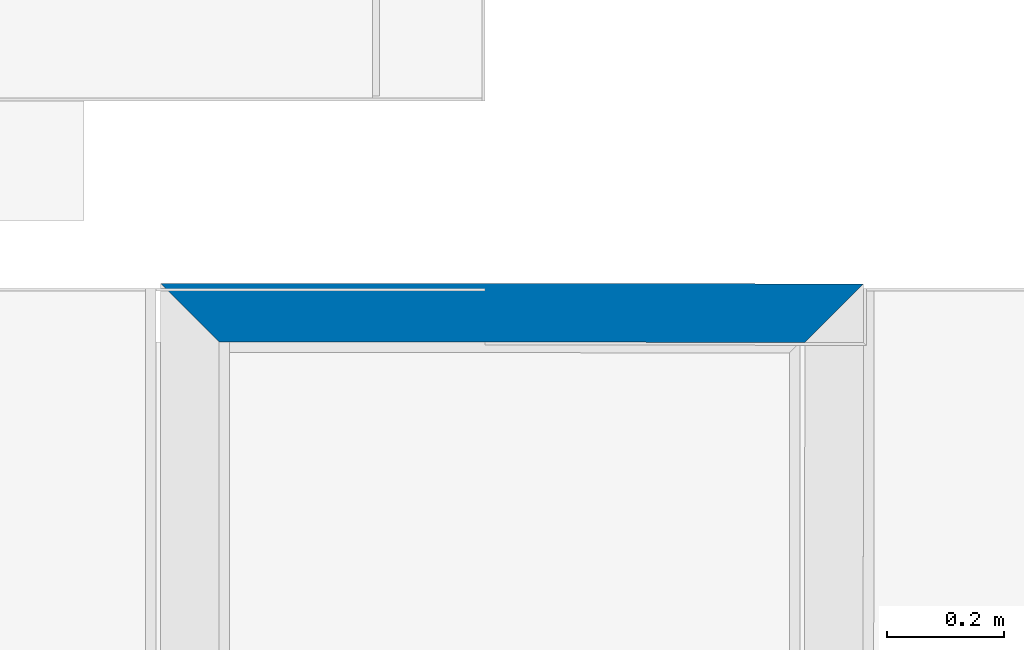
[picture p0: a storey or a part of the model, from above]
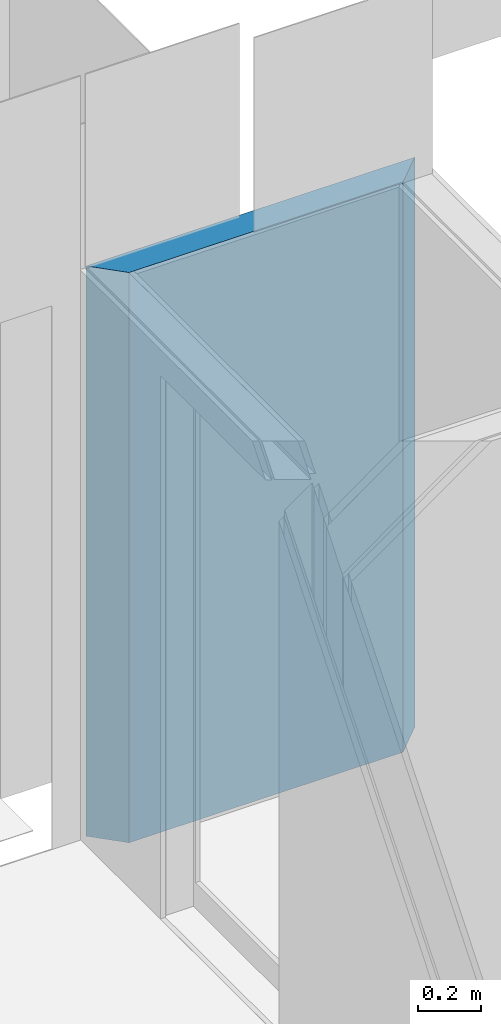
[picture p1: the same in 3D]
Properties of the parts of a building model (IFC2X3), part 1 of 2

# File
Description: ViewDefinition [CoordinationView_V2.0, SpaceBoundary2ndLevelAddOnView], Option [Elements to export: Filtered elements], Option [Partial Structure Display: Entire Model], Option [IFC Domain: All], Option [Structural Function: All Elements], Option [Convert Grid elements: On], Option [Convert IFC Annotations and Archicad 2D elements: Off], Option [Convert 2D symbols of Doors and Windows: Off], Option [Export geometries that Participates in Collision Detection only: Off], Option [Split complex elements: On], Option [IFC Domain For Space Containment: Custom], Option [Elements in Solid Element Operations: Extruded/revolved], Option [Elements with junctions: Extruded/revolved without junctions], Option [IFC Model position: Survey Point and Project Origin], Option [Curtain Wall export mode: Container Element], Option [Railing export mode: Container Element], Option [Stair export mode: Container Element], Option [Properties To Export: All properties], Option [Space containment: Off], Option [Geometry to type objects: Off], Option [Element Properties: Visible Only], Option [Building Material Properties: Off], Option [Element Parameters: Off], Option [Component Parameters: Off], Option [IFC Base Quantities: Off], Option [Door Window Parameters: On], Option [IFC Space boundaries: On], Option [Archicad Zone Categories as IFC Space classification data: Off], Option [Element Classifications: On]
File name: C:\Users\karle\Documents\KARLERK TARBE OÜ\Projektid\Ilmajaam\Ilmajaam TP\355_TP_SA_Paldiski-mnt-245-põrandad-seinad-20231201.ifc
Time: 2023-12-01T14:40:17
Author: Andres Rihe (allikirjastatud digitaalselt)
Organization: Building Designer Office
Written by: DDS_IFC v3.0
Made in: IFC file generated by Graphisoft Archicad 26.0.0 INT FULL Windows version (IFC add-on version: 4019 INT FULL).
Authorization: Andres Rihe (allikirjastatud digitaalselt)

# IfcProject, Ilmavaatlusjaama peahoone rekonstrueerimine
Description: Arhitektuur; Phase: Eelprojekt

# IfcSite, Paldiski mnt 245/1, Tallinn, Harjumaa
Description: Ühiskondlike ehitiste maa 100%; RefLatitude: 59, 26, 0, 0; RefLongitude: 24, 45, 0, 0; RefElevation: 0 mm; Classification: C Existing site/buildings/services (CAWS); 1.0.1 IfcSite (kinnistu) (RKAS BIM + ARCHICAD Classification 25 + v 2.0)
AR_Kinnistu - 010_Katastritunnus: 78406:605:0160; 020_Pindala: 24079 m2; 025_Max_kõrgus: 8600 mm; 015_Ehitatav_pindala: 1045.7 m2

# IfcBuilding, RKAS Hoone üldnimetus (kasutust iseloomustav) -> IFC Project Manager -> SOLIBRI
Classification: 1.0.2 IfcBuilding (hoone) (RKAS BIM + ARCHICAD Classification 25 + v 2.0)
AR_Hoone - 035_Sprinkler: no; 001_Nimetus: 12201 Büroohoone; 030_Hoone_aadress: Paldiski mnt 245/1 (katastriüksuse tunnus 78406:605:0160 ), Haabersti linnaosa, Tallinn, Eesti Vabariik; 040_Kõrgus: 8600 mm; ?: 1004.1 m2; 050_Neto_pindala: 1090.4 m2; 055_Neto_ruumala: 5563.9 m3

# IfcBuildingStorey (4)
In: RKAS Hoone üldnimetus (kasutust iseloomustav) -> IFC Project Manager -> SOLIBRI
Name | Elevation (mm) | Classification
Katusekorrus | 6240
Esimene korrus | 0 | 1.0.3 IfcBuildingStorey (korrus) (RKAS BIM + ARCHICAD Classification 25 + v 2.0)
Vundament | -1200 | 1.0.3 IfcBuildingStorey (korrus) (RKAS BIM + ARCHICAD Classification 25 + v 2.0)
Teine korrus | 3300 | 1.0.3 IfcBuildingStorey (korrus) (RKAS BIM + ARCHICAD Classification 25 + v 2.0)

# IfcBuildingElementProxy: Cube 26, REEPER
In: Esimene korrus
Classification: 1.02.1 IfcBuildingElementProxyType (reeper) (RKAS BIM + ARCHICAD Classification)
AR - 001_Nimetus: REEPER
Pset_BuildingElementProxyCommon - Reference: Cube 26
AR_Reeper - 01_X-(L-EST): 3000; 02_Y-(L-EST): 1000; 03_Z-(EH2000): 7000; 04_Nurk(◦): 0
AC_Pset_RenovationAndPhasing - Renovation Status: New

# IfcBuildingElementProxy: SA- PM-4 porivaip 20, PM-4
In: Teine korrus
Classification: 1.14 IfcOpeningElement (avaelement) (RKAS BIM + ARCHICAD Classification); Material: SA- PM-4 porivaip
Pset_BuildingElementProxyCommon - Reference: SA- PM-4 porivaip
AR - 001_Nimetus: PM-4
AC_Pset_RenovationAndPhasing - Renovation Status: New

# IfcBuildingElementProxy: SA- PM-7 plaat 15x15 8, PM-7
In: Teine korrus
Classification: 1.14 IfcOpeningElement (avaelement) (RKAS BIM + ARCHICAD Classification); Material: SA- PM-7 plaat 15x15
Pset_BuildingElementProxyCommon - Reference: SA- PM-7 plaat 15x15
AR - 001_Nimetus: Põrandakatte materjal
AC_Pset_RenovationAndPhasing - Renovation Status: New

# IfcCovering: GENERIC - PREFABRICATED (106)
Type - PredefinedType: CLADDING
Classification: 1.05 IfcCoveringType.CLADDING (seina viimistlus) (RKAS BIM + ARCHICAD Classification); Material: GENERIC - PREFABRICATED
AR_Viimistlus - 215_Tulekindlusklass: B-s1,d0; 230_Niiskuskindel: no; 200_Materjal (MUDELIS): GENERIC - PREFABRICATED
AC_Pset_RenovationAndPhasing - Renovation Status: New
Name | In | Reference | AR_Viimistlus, 001_Nimetus = AR, 001_Nimetus | 200_Materjal | 205_Tähis | 220_Viimistlus | 900_Tootja | 905_Mudel | 910_Tooteinfo = 915_Kasutus-ja_hooldusjuhend | 240_Märghõõrdekindlus | 245_Aluspind | 210_Paksus (mm)
SM5 | Teine korrus | SM5 | Seinavärv | Veepõhine värv | SM5 | Poolmatt NCS S 1002-y20r (soe valge) | Tikkurila | Vivacolor interior | https://tikkurila.ee/ | 1.klass | Pahteldatud kipsplaat/sein | 1
105 x SM1 | Esimene korrus | GENERIC - PREFABRICATED | Seinapaneel | Akustiline vilt, spoon | SM1 | Tehase viimistlus | Vaga | Vesi | https://vaga-panel.ee/vaga-vesi/ | Undefined | Viimistletud sein | 23

# IfcCovering: KON-00_GENEERILINE - KONSTRUKTSIOON 100 (4)
In: Esimene korrus
Type - PredefinedType: CLADDING
Classification: 1.05 IfcCoveringType.CLADDING (seina viimistlus) (RKAS BIM + ARCHICAD Classification); Material: KON-00_GENEERILINE - KONSTRUKTSIOON
AC_Pset_RenovationAndPhasing - Renovation Status: Existing
Pset_CoveringCommon - Reference: KON-00; TotalThickness: 100 mm
AR_Viimistlus - 230_Niiskuskindel: no; 900_Tootja: Undefined; 905_Mudel: Undefined; 910_Tooteinfo: Undefined; 915_Kasutus-ja_hooldusjuhend: Undefined; 200_Materjal (MUDELIS): KON-00_GENEERILINE - KONSTRUKTSIOON
Name | AR_Viimistlus, 001_Nimetus = AR, 001_Nimetus | 225_Pindala (m2)
SM-3 | SM-3 | 4.35325
SM-3 | SM-3 | 2.45625
SS-59 | SS-59 | 4.35945
SS-63 | SS-63 | 2.18122

# IfcCovering: KON-00_GENEERILINE - KONSTRUKTSIOON 20, SM-1
In: Esimene korrus
Type - PredefinedType: CLADDING
Classification: 1.05 IfcCoveringType.CLADDING (seina viimistlus) (RKAS BIM + ARCHICAD Classification); Material: KON-00_GENEERILINE - KONSTRUKTSIOON
AR_Viimistlus - 230_Niiskuskindel: no; 001_Nimetus: SM-1; 900_Tootja: Undefined; 905_Mudel: Undefined; 910_Tooteinfo: Undefined; 915_Kasutus-ja_hooldusjuhend: Undefined; 200_Materjal (MUDELIS): KON-00_GENEERILINE - KONSTRUKTSIOON; 225_Pindala: 14.9372 m2
Pset_CoveringCommon - Reference: KON-00; TotalThickness: 20 mm
AR - 001_Nimetus: SM-1
AC_Pset_RenovationAndPhasing - Renovation Status: Existing

# IfcCovering: PL-2 10 x 60 (2)
In: Esimene korrus
Type - PredefinedType: CEILING
Classification: 1.04 IfcCoveringType.CEILING (ripplagi) (RKAS BIM + ARCHICAD Classification); Material: RAL 9007
Pset_CoveringCommon - Reference: RL-1; Material: Teras
AR_Viimistlus - 001_Nimetus: Ripplae liist; 235_Karkass: Undefined; 900_Tootja: Ecophon; 905_Mudel: T24, L24; 200_Materjal (MUDELIS): RAL 9007
AC_Pset_RenovationAndPhasing - Renovation Status: New
AR - 001_Nimetus: Ripplae liist

# IfcCovering: PL-5 4 x 70 (10)
In: Teine korrus
Type - PredefinedType: CEILING
Classification: 1.04 IfcCoveringType.CEILING (ripplagi) (RKAS BIM + ARCHICAD Classification); Material: SA- PM-2 vinüül hex
Pset_CoveringCommon - Reference: RL-1; Material: Teras
AR_Viimistlus - 001_Nimetus: Ripplae liist; 235_Karkass: Undefined; 900_Tootja: Ecophon; 905_Mudel: T24, L24; 200_Materjal (MUDELIS): SA- PM-2 vinüül hex
AR - 001_Nimetus: Ripplae liist
AC_Pset_RenovationAndPhasing - Renovation Status: New

# IfcCovering: SA- Laminaat SM13(beez laminaat) 12 (11)
In: Esimene korrus
Type - PredefinedType: CLADDING
Classification: 1.05 IfcCoveringType.CLADDING (seina viimistlus) (RKAS BIM + ARCHICAD Classification); Material: SA- Laminaat SM13(beez laminaat)
AR_Viimistlus - 230_Niiskuskindel: no; 001_Nimetus: Seinapaneel; 900_Tootja: abet laminati; 905_Mudel: abet laminati 478 grigio chiaro; fin sei.; 910_Tooteinfo: https://abetlaminati.com/; 915_Kasutus-ja_hooldusjuhend: https://abetlaminati.com/; 200_Materjal (MUDELIS): SA- Laminaat SM13(beez laminaat)
Pset_CoveringCommon - Reference: SA- Laminaat SM13(beez laminaat); TotalThickness: 12 mm
AR - 001_Nimetus: Seinapaneel
AC_Pset_RenovationAndPhasing - Renovation Status: New
Name | 225_Pindala (m2)
SM13 | 2.73049
SM13 | 2.07402
SM13 | 2.71213
SM13 | 2.35932
SM13 | 1.81026
SM13 | 0.977507
SM13 | 2.01618
SM13 | 2.77418
SM13 | 4.56394
SM13 | 3.01871
SM13 | 1.49167

# IfcCovering: SA- Laminaat SM2(kollane laminaat) 10 (2)
In: Esimene korrus
Type - PredefinedType: CLADDING
Classification: 1.05 IfcCoveringType.CLADDING (seina viimistlus) (RKAS BIM + ARCHICAD Classification); Material: SA- Laminaat SM2(kollane laminaat)
AR_Viimistlus - 230_Niiskuskindel: no; 001_Nimetus: Seinapaneel; 900_Tootja: Abet Laminati; 905_Mudel: 1801 giallo ocra; fin sei; 910_Tooteinfo: https://de.abetlaminati.com/decori/meg-colours-giallo-ocra-1801/; 915_Kasutus-ja_hooldusjuhend: https://de.abetlaminati.com/decori/meg-colours-giallo-ocra-1801/; 200_Materjal (MUDELIS): SA- Laminaat SM2(kollane laminaat)
AR - 001_Nimetus: Seinapaneel
AC_Pset_RenovationAndPhasing - Renovation Status: New
Pset_CoveringCommon - Reference: SA- Laminaat SM2(kollane laminaat); TotalThickness: 10 mm
Name | 225_Pindala (m2)
SM2 | 6.49925
SM2 | 2.78749

# IfcCovering: SA- Laminaat SM2(kollane laminaat) 12 (9)
Type - PredefinedType: CLADDING
Classification: 1.05 IfcCoveringType.CLADDING (seina viimistlus) (RKAS BIM + ARCHICAD Classification); Material: SA- Laminaat SM2(kollane laminaat)
AR_Viimistlus - 230_Niiskuskindel: no; 001_Nimetus: Seinapaneel; 900_Tootja: Abet Laminati; 905_Mudel: 1801 giallo ocra; fin sei; 910_Tooteinfo: https://de.abetlaminati.com/decori/meg-colours-giallo-ocra-1801/; 915_Kasutus-ja_hooldusjuhend: https://de.abetlaminati.com/decori/meg-colours-giallo-ocra-1801/; 200_Materjal (MUDELIS): SA- Laminaat SM2(kollane laminaat)
Pset_CoveringCommon - Reference: SA- Laminaat SM2(kollane laminaat); TotalThickness: 12 mm
AR - 001_Nimetus: Seinapaneel
AC_Pset_RenovationAndPhasing - Renovation Status: New
Name | In | 225_Pindala (m2)
SM2 | Teine korrus | 5.54141
SM2 | Teine korrus | 3.08782
SM2 | Teine korrus | 5.65656
SM2 | Teine korrus | 2.99939
SM2 | Esimene korrus | 2.3313
SM2 | Esimene korrus | 2.69522
SM2 | Esimene korrus | 3.71926
SM2 | Esimene korrus | 2.70783
SM2 | Esimene korrus | 1.31737

# IfcCovering: SA- Laminaat SM2(kollane laminaat) 12, SM2
In: Esimene korrus
Type - PredefinedType: FLOORING
Classification: 1.06 IfcCoveringType.FLOORING (põrandakatted) (RKAS BIM + ARCHICAD Classification); Material: SA- Laminaat SM2(kollane laminaat)
Pset_CoveringCommon - Reference: SA- Laminaat SM2(kollane laminaat); TotalThickness: 12 mm
AR_Viimistlus - 001_Nimetus: SM2; 200_Materjal: SA- Laminaat SM2(kollane laminaat); 205_Tähis: SA- Laminaat SM2(kollane laminaat); 215_Tulekindlusklass: Undefined; 220_Viimistlus: Undefined; 230_Niiskuskindel: no; 900_Tootja: Undefined; 905_Mudel: Undefined; 910_Tooteinfo: Undefined; 915_Kasutus-ja_hooldusjuhend: Undefined; 240_Märghõõrdekindlus: Undefined; 245_Aluspind: Undefined; 200_Materjal (MUDELIS): SA- Laminaat SM2(kollane laminaat); 225_Pindala: 0.213811 m2; 210_Paksus: 12 mm
AC_Pset_RenovationAndPhasing - Renovation Status: Existing
AR - 001_Nimetus: SM2

# IfcCovering: SA- Laminaat SM2(kollane laminaat) 20, SM2
In: Esimene korrus
Type - PredefinedType: FLOORING
Classification: 1.06 IfcCoveringType.FLOORING (põrandakatted) (RKAS BIM + ARCHICAD Classification); Material: SA- Laminaat SM2(kollane laminaat)
Pset_CoveringCommon - Reference: SA- Laminaat SM2(kollane laminaat); TotalThickness: 20 mm
AR_Viimistlus - 001_Nimetus: SM2; 200_Materjal: SA- Laminaat SM2(kollane laminaat); 205_Tähis: SA- Laminaat SM2(kollane laminaat); 215_Tulekindlusklass: Undefined; 220_Viimistlus: Undefined; 230_Niiskuskindel: no; 900_Tootja: Undefined; 905_Mudel: Undefined; 910_Tooteinfo: Undefined; 915_Kasutus-ja_hooldusjuhend: Undefined; 240_Märghõõrdekindlus: Undefined; 245_Aluspind: Undefined; 200_Materjal (MUDELIS): SA- Laminaat SM2(kollane laminaat); 225_Pindala: 0.435872 m2; 210_Paksus: 20 mm
AR - 001_Nimetus: SM2
AC_Pset_RenovationAndPhasing - Renovation Status: Existing

# IfcCovering: SA- Laminaat SM2(kollane laminaat) Polygonal, SM2
In: Teine korrus
Type - PredefinedType: CLADDING
Classification: 1.05 IfcCoveringType.CLADDING (seina viimistlus) (RKAS BIM + ARCHICAD Classification); Material: SA- Laminaat SM2(kollane laminaat)
Pset_CoveringCommon - Reference: SA- Laminaat SM2(kollane laminaat); TotalThickness: 12 mm
AR_Viimistlus - 001_Nimetus: Seinapaneel; 200_Materjal: 9mm mdf plaat kaetud kõrgsurve laminaadiga; 205_Tähis: SM2; 215_Tulekindlusklass: B-s1, d0; 220_Viimistlus: Puudub; 230_Niiskuskindel: yes; 900_Tootja: Abet Laminati; 905_Mudel: 1801 giallo ocra; fin sei; 910_Tooteinfo: https://de.abetlaminati.com/decori/meg-colours-giallo-ocra-1801/; 915_Kasutus-ja_hooldusjuhend: https://de.abetlaminati.com/decori/meg-colours-giallo-ocra-1801/; 240_Märghõõrdekindlus: 1.klass; 245_Aluspind: Kertopuu/teras karkass; 200_Materjal (MUDELIS): SA- Laminaat SM2(kollane laminaat); 225_Pindala: 3.47217 m2; 210_Paksus: 10 mm
AR - 001_Nimetus: Seinapaneel
AC_Pset_RenovationAndPhasing - Renovation Status: New

# IfcCovering: SA- Laudis SM3(vert. laudis) 18 (25)
In: Esimene korrus
Type - PredefinedType: CLADDING
Classification: 1.05 IfcCoveringType.CLADDING (seina viimistlus) (RKAS BIM + ARCHICAD Classification); Material: SA- Laudis SM3(vert. laudis)
Pset_CoveringCommon - TotalThickness: 18 mm
AR_Viimistlus - 230_Niiskuskindel: no; 900_Tootja: Puumarket; 200_Materjal (MUDELIS): SA- Laudis SM3(vert. laudis)
AC_Pset_RenovationAndPhasing - Renovation Status: New
Name | Reference | AR_Viimistlus, 001_Nimetus = AR, 001_Nimetus | 905_Mudel | 910_Tooteinfo = 915_Kasutus-ja_hooldusjuhend | 225_Pindala (m2)
SM14 | SA- Laudis SM3(vert. laudis) | Laudis | PTGV12x120, Tikkurila supi saunavaha (hall) ühe kihina | https://puumarket.ee/toode/sisevoodrilaud-kuusk-ptgv-12x120x3000mm/ | 1.56151
SM14 | SA- Laudis SM3(vert. laudis) | Laudis | PTGV12x120, Tikkurila supi saunavaha (hall) ühe kihina | https://puumarket.ee/toode/sisevoodrilaud-kuusk-ptgv-12x120x3000mm/ | 0.059546
SM14 | SA- Laudis SM3(vert. laudis) | Laudis | PTGV12x120, Tikkurila supi saunavaha (hall) ühe kihina | https://puumarket.ee/toode/sisevoodrilaud-kuusk-ptgv-12x120x3000mm/ | 0.0537709
SM14 | SA- Laudis SM3(vert. laudis) | Laudis | PTGV12x120, Tikkurila supi saunavaha (hall) ühe kihina | https://puumarket.ee/toode/sisevoodrilaud-kuusk-ptgv-12x120x3000mm/ | 0.347141
SM14 | SA- Laudis SM3(vert. laudis) | Laudis | PTGV12x120, Tikkurila supi saunavaha (hall) ühe kihina | https://puumarket.ee/toode/sisevoodrilaud-kuusk-ptgv-12x120x3000mm/ | 1.19245
2 x SM14 | SA- Laudis SM3(vert. laudis) | Laudis | PTGV12x120, Tikkurila supi saunavaha (hall) ühe kihina | https://puumarket.ee/toode/sisevoodrilaud-kuusk-ptgv-12x120x3000mm/ | 0
SM14 | SA- Laudis SM3(vert. laudis) | Laudis | PTGV12x120, Tikkurila supi saunavaha (hall) ühe kihina | https://puumarket.ee/toode/sisevoodrilaud-kuusk-ptgv-12x120x3000mm/ | 1.90986
SM14 | SA- Laudis SM3(vert. laudis) | Laudis | PTGV12x120, Tikkurila supi saunavaha (hall) ühe kihina | https://puumarket.ee/toode/sisevoodrilaud-kuusk-ptgv-12x120x3000mm/ | 2.18302
SM14 | SA- Laudis SM3(vert. laudis) | Laudis | PTGV12x120, Tikkurila supi saunavaha (hall) ühe kihina | https://puumarket.ee/toode/sisevoodrilaud-kuusk-ptgv-12x120x3000mm/ | 1.96838
SM14 | SA- Laudis SM3(vert. laudis) | Laudis | PTGV12x120, Tikkurila supi saunavaha (hall) ühe kihina | https://puumarket.ee/toode/sisevoodrilaud-kuusk-ptgv-12x120x3000mm/ | 2.14168
SM14 | SA- Laudis SM3(vert. laudis) | Laudis | PTGV12x120, Tikkurila supi saunavaha (hall) ühe kihina | https://puumarket.ee/toode/sisevoodrilaud-kuusk-ptgv-12x120x3000mm/ | 2.68847
SM14 | SA- Laudis SM3(vert. laudis) | Laudis | PTGV12x120, Tikkurila supi saunavaha (hall) ühe kihina | https://puumarket.ee/toode/sisevoodrilaud-kuusk-ptgv-12x120x3000mm/ | 2.68978
SM14 | SA- Laudis SM3(vert. laudis) | Laudis | PTGV12x120, Tikkurila supi saunavaha (hall) ühe kihina | https://puumarket.ee/toode/sisevoodrilaud-kuusk-ptgv-12x120x3000mm/ | 2.03073
SM14 | SA- Laudis SM3(vert. laudis) | Laudis | PTGV12x120, Tikkurila supi saunavaha (hall) ühe kihina | https://puumarket.ee/toode/sisevoodrilaud-kuusk-ptgv-12x120x3000mm/ | 2.66716
SM14 | SA- Laudis SM3(vert. laudis) | Laudis | PTGV12x120, Tikkurila supi saunavaha (hall) ühe kihina | https://puumarket.ee/toode/sisevoodrilaud-kuusk-ptgv-12x120x3000mm/ | 2.06625
SM14 | SA- Laudis SM3(vert. laudis) | Laudis | PTGV12x120, Tikkurila supi saunavaha (hall) ühe kihina | https://puumarket.ee/toode/sisevoodrilaud-kuusk-ptgv-12x120x3000mm/ | 2.17927
SM14 | SA- Laudis SM3(vert. laudis) | Laudis | PTGV12x120, Tikkurila supi saunavaha (hall) ühe kihina | https://puumarket.ee/toode/sisevoodrilaud-kuusk-ptgv-12x120x3000mm/ | 2.13973
SM14 | SA- Laudis SM3(vert. laudis) | Laudis | PTGV12x120, Tikkurila supi saunavaha (hall) ühe kihina | https://puumarket.ee/toode/sisevoodrilaud-kuusk-ptgv-12x120x3000mm/ | 1.06101
SM3 | SM3 | Saunalaudis | 15×120 Kattev laius 110mm Puuliik Haab Profiil STS4 | https://puumarket.ee/toode/sauna-voodrilaud-termohaab-sts4-15x120x2700mm/ | 3.33925
SM3 | SM3 | Saunalaudis | 15×120 Kattev laius 110mm Puuliik Haab Profiil STS4 | https://puumarket.ee/toode/sauna-voodrilaud-termohaab-sts4-15x120x2700mm/ | 6.80479
SM3 | SM3 | Saunalaudis | 15×120 Kattev laius 110mm Puuliik Haab Profiil STS4 | https://puumarket.ee/toode/sauna-voodrilaud-termohaab-sts4-15x120x2700mm/ | 3.32311
SM3 | SM3 | Saunalaudis | 15×120 Kattev laius 110mm Puuliik Haab Profiil STS4 | https://puumarket.ee/toode/sauna-voodrilaud-termohaab-sts4-15x120x2700mm/ | 0.1644
SM3 | SM3 | Saunalaudis | 15×120 Kattev laius 110mm Puuliik Haab Profiil STS4 | https://puumarket.ee/toode/sauna-voodrilaud-termohaab-sts4-15x120x2700mm/ | 6.85554
SM3 | SM3 | Saunalaudis | 15×120 Kattev laius 110mm Puuliik Haab Profiil STS4 | https://puumarket.ee/toode/sauna-voodrilaud-termohaab-sts4-15x120x2700mm/ | 5.06151

# IfcCovering: SA- Laudlagi 15, l2
In: Esimene korrus
Type - PredefinedType: CEILING
Classification: 1.04 IfcCoveringType.CEILING (ripplagi) (RKAS BIM + ARCHICAD Classification); Material: SA- Laudlagi
Pset_CoveringCommon - Reference: L2; Material: Puit; TotalThickness: 15 mm
AR_Viimistlus - 001_Nimetus: Laudis lagi; 235_Karkass: Puitkarkass/kertopuu; 900_Tootja: Puumarket; 905_Mudel: 15×120, Haab Profiil STS4, termotöödeldud; 200_Materjal (MUDELIS): SA- Laudlagi
AC_Pset_RenovationAndPhasing - Renovation Status: Existing
AR - 001_Nimetus: Laudis lagi

# IfcCovering: SA- PM-1 plaatpõrand 8, PM-1
In: Esimene korrus
Type - PredefinedType: FLOORING
Classification: 1.06 IfcCoveringType.FLOORING (põrandakatted) (RKAS BIM + ARCHICAD Classification); Material: SA- PM-1 plaatpõrand
AR - 001_Nimetus: Põrandakatte materjal
AR_Viimistlus - 001_Nimetus: Põrandakatte materjal; 200_Materjal: Keraamika; 205_Tähis: PM-1; 215_Tulekindlusklass: Puudub; 220_Viimistlus: Tehase viimistlus; 230_Niiskuskindel: yes; 900_Tootja: Topcer; 905_Mudel: heksagon100x115x8mm kiviparkett kolme tooni segu Toonid: 14(tumehall), 16(vana valge), 21 (kollane); 910_Tooteinfo: https://www.topcer.com/sizes_and_shapes.php; 915_Kasutus-ja_hooldusjuhend: https://www.topcer.com/sizes_and_shapes.php; 240_Märghõõrdekindlus: Undefined; 245_Aluspind: betoon; 200_Materjal (MUDELIS): SA- PM-1 plaatpõrand; 225_Pindala: 49.777 m2; 210_Paksus: 8 mm
AC_Pset_RenovationAndPhasing - Renovation Status: New
Pset_CoveringCommon - Reference: SA- PM-1 plaatpõrand; TotalThickness: 8 mm

# IfcCovering: SA- PM-2 vinüül hex 3 (11)
In: Teine korrus
Type - PredefinedType: FLOORING
Classification: 1.06 IfcCoveringType.FLOORING (põrandakatted) (RKAS BIM + ARCHICAD Classification); Material: SA- PM-2 vinüül hex
Pset_CoveringCommon - Reference: SA- PM-2 vinüül hex; TotalThickness: 3 mm
AR_Viimistlus - 001_Nimetus: Põrandakatte materjal; 200_Materjal: PVC; 205_Tähis: PM-2; 215_Tulekindlusklass: Bfl-s1; 220_Viimistlus: Tehase viimistlus; 230_Niiskuskindel: no; 900_Tootja: Beauflor; 905_Mudel: Sonipro nimes 909L; 910_Tooteinfo: https://www.beauflor.com/global/en/products/pro/sonipro/sonipro-nimes-909l-4000?_gl=1*r97tby*_up*MQ..*_ga*ODYxNTk5OC4xNzAwNTY2Mzc3*_ga_B0012XKCK9*MTcwMDU2NjM3Ni4xLjAuMTcwMDU2NjM3Ni4wLjAuMA..; 915_Kasutus-ja_hooldusjuhend: https://www.beauflor.com/global/en/products/pro/sonipro/sonipro-nimes-909l-4000?_gl=1*r97tby*_up*MQ..*_ga*ODYxNTk5OC4xNzAwNTY2Mzc3*_ga_B0012XKCK9*MTcwMDU2NjM3Ni4xLjAuMTcwMDU2NjM3Ni4wLjAuMA..; 240_Märghõõrdekindlus: Undefined; 245_Aluspind: Tasandussegu; 200_Materjal (MUDELIS): SA- PM-2 vinüül hex; 210_Paksus: 3 mm
AR - 001_Nimetus: Põrandakatte materjal
AC_Pset_RenovationAndPhasing - Renovation Status: New
Name | 225_Pindala (m2)
PM-2 | 34.7091
PM-2 | 32.8767
PM-2 | 45.9795
PM-2 | 3.19659
PM-2 | 33.3777
PM-2 | 16.8821
PM-2 | 3.27844
PM-2 | 17.2698
PM-2 | 26.4244
PM-2 | 17.0508
PM-2 | 16.1256

# IfcCovering: SA- PM-3 vinüül rice 3 (5)
In: Teine korrus
Type - PredefinedType: FLOORING
Classification: 1.06 IfcCoveringType.FLOORING (põrandakatted) (RKAS BIM + ARCHICAD Classification); Material: SA- PM-3 vinüül rice
Pset_CoveringCommon - Reference: SA- PM-3 vinüül rice; TotalThickness: 3 mm
AC_Pset_RenovationAndPhasing - Renovation Status: New
AR - 001_Nimetus: Põrandakatte materjal
AR_Viimistlus - 001_Nimetus: Põrandakatte materjal; 200_Materjal: PVC heterogeenne; 205_Tähis: PM-3; 215_Tulekindlusklass: Bfl-s1; 220_Viimistlus: Tehase viimistlus; 230_Niiskuskindel: no; 900_Tootja: Beauflor; 905_Mudel: Blacktex Safira 990D; 910_Tooteinfo: https://www.beauflor.com/global/en/products/ultra/blacktex/safira-990d?_gl=1*b20gb7*_up*MQ..*_ga*MTA3ODgyOTQ2My4xNjk4MzEwOTcw*_ga_B0012XKCK9*MTY5ODMxMDk3MC4xLjAuMTY5ODMxMDk3MC4wLjAuMA; 915_Kasutus-ja_hooldusjuhend: https://www.beauflor.com/global/en/products/ultra/blacktex/safira-990d?_gl=1*b20gb7*_up*MQ..*_ga*MTA3ODgyOTQ2My4xNjk4MzEwOTcw*_ga_B0012XKCK9*MTY5ODMxMDk3MC4xLjAuMTY5ODMxMDk3MC4wLjAuMA; 240_Märghõõrdekindlus: Undefined; 245_Aluspind: Tasandussegu; 200_Materjal (MUDELIS): SA- PM-3 vinüül rice; 210_Paksus: 2.8 mm
Name | 225_Pindala (m2)
PM-3 | 6.75571
PM-3 | 15.0021
PM-3 | 14.456
PM-3 | 6.63345
PM-3 | 6.49695

# IfcCovering: SA- PM-3 vinüül rice 4, PM-3
In: Teine korrus
Type - PredefinedType: FLOORING
Classification: 1.06 IfcCoveringType.FLOORING (põrandakatted) (RKAS BIM + ARCHICAD Classification); Material: SA- PM-3 vinüül rice
AC_Pset_RenovationAndPhasing - Renovation Status: New
AR - 001_Nimetus: Põrandakatte materjal
AR_Viimistlus - 001_Nimetus: Põrandakatte materjal; 200_Materjal: PVC heterogeenne; 205_Tähis: PM-3; 215_Tulekindlusklass: Bfl-s1; 220_Viimistlus: Tehase viimistlus; 230_Niiskuskindel: no; 900_Tootja: Beauflor; 905_Mudel: Blacktex Safira 990D; 910_Tooteinfo: https://www.beauflor.com/global/en/products/ultra/blacktex/safira-990d?_gl=1*b20gb7*_up*MQ..*_ga*MTA3ODgyOTQ2My4xNjk4MzEwOTcw*_ga_B0012XKCK9*MTY5ODMxMDk3MC4xLjAuMTY5ODMxMDk3MC4wLjAuMA; 915_Kasutus-ja_hooldusjuhend: https://www.beauflor.com/global/en/products/ultra/blacktex/safira-990d?_gl=1*b20gb7*_up*MQ..*_ga*MTA3ODgyOTQ2My4xNjk4MzEwOTcw*_ga_B0012XKCK9*MTY5ODMxMDk3MC4xLjAuMTY5ODMxMDk3MC4wLjAuMA; 240_Märghõõrdekindlus: Undefined; 245_Aluspind: Tasandussegu; 200_Materjal (MUDELIS): SA- PM-3 vinüül rice; 225_Pindala: 15.6772 m2; 210_Paksus: 2.8 mm
Pset_CoveringCommon - Reference: SA- PM-3 vinüül rice; TotalThickness: 4 mm

# IfcCovering: SA- PM-4 porivaip 10, PM-4
In: Esimene korrus
Type - PredefinedType: FLOORING
Classification: 1.06 IfcCoveringType.FLOORING (põrandakatted) (RKAS BIM + ARCHICAD Classification); Material: SA- PM-4 porivaip
Pset_CoveringCommon - Reference: SA- PM-4 porivaip; TotalThickness: 10 mm
AR_Viimistlus - 001_Nimetus: Porivaip; 200_Materjal: vaip, plastik; 205_Tähis: PM-4; 215_Tulekindlusklass: A2-s1,d0; 220_Viimistlus: Tehase viimistlus; 230_Niiskuskindel: yes; 900_Tootja: Muovihaka; 905_Mudel: Silver Brush Carpet; 910_Tooteinfo: https://www.muovihaka.com/tuulikaappimatot/silver-tekstiili-14mm-tuulikaappimatto; 915_Kasutus-ja_hooldusjuhend: https://www.muovihaka.com/tuulikaappimatot/silver-tekstiili-14mm-tuulikaappimatto; 240_Märghõõrdekindlus: Undefined; 245_Aluspind: Tasandussegu/betoon; 200_Materjal (MUDELIS): SA- PM-4 porivaip; 225_Pindala: 4.05541 m2; 210_Paksus: 17 mm
AR - 001_Nimetus: Porivaip
AC_Pset_RenovationAndPhasing - Renovation Status: New

# IfcCovering: SA- PM-5 plaat 30x30 8 (20)
In: Esimene korrus
Type - PredefinedType: FLOORING
Classification: 1.06 IfcCoveringType.FLOORING (põrandakatted) (RKAS BIM + ARCHICAD Classification); Material: SA- PM-5 plaat 30x30
Pset_CoveringCommon - Reference: SA- PM-5 plaat 30x30; TotalThickness: 8 mm
AR_Viimistlus - 001_Nimetus: Põrandakatte materjal; 200_Materjal: Täismassplaat; 205_Tähis: PM-5; 215_Tulekindlusklass: Puudub; 220_Viimistlus: Tehase viimistlus; 230_Niiskuskindel: yes; 900_Tootja: Topcer; 905_Mudel: Hotisontaal: topcer ST: toon;14 (tumehall) 296x296; 910_Tooteinfo: https://www.topcer.com/sizes_and_shapes.php; 915_Kasutus-ja_hooldusjuhend: https://www.topcer.com/sizes_and_shapes.php; 240_Märghõõrdekindlus: Undefined; 245_Aluspind: Betoon; 200_Materjal (MUDELIS): SA- PM-5 plaat 30x30; 225_Pindala: 0.354 m2; 210_Paksus: 8.5 mm
AR - 001_Nimetus: Põrandakatte materjal
AC_Pset_RenovationAndPhasing - Renovation Status: New

# IfcCovering: SA- PM-6 vinüül 3 (13)
In: Esimene korrus
Type - PredefinedType: FLOORING
Classification: 1.06 IfcCoveringType.FLOORING (põrandakatted) (RKAS BIM + ARCHICAD Classification); Material: SA- PM-6 vinüül
AR_Viimistlus - 001_Nimetus: Põrandakate; 200_Materjal: PVC; 205_Tähis: PM-6; 215_Tulekindlusklass: Bfl-s1; 220_Viimistlus: Tehase viimistlus; 230_Niiskuskindel: yes; 900_Tootja: gerflor; 905_Mudel: TARALAY SAFETY COMPACT DESIGN 6171 LOFTER DARK GRAY; 910_Tooteinfo: https://www.gerflor.fr/produits/taralay-securite-compact-design-6171-lofter-dark-grey-hb926171; 915_Kasutus-ja_hooldusjuhend: https://www.gerflor.fr/produits/taralay-securite-compact-design-6171-lofter-dark-grey-hb926171; 240_Märghõõrdekindlus: Undefined; 245_Aluspind: Tasandussegu; 200_Materjal (MUDELIS): SA- PM-6 vinüül; 210_Paksus: 2 mm
Pset_CoveringCommon - Reference: PM-6; TotalThickness: 3 mm
AR - 001_Nimetus: Põrandakate
Name | 225_Pindala (m2) | Renovation Status
PM-6 | 43.633 | New
PM-6 | 1.93066 | New
PM-6 | 21.4308 | New
PM-6 | 36.7239 | New
PM-6 | 31.0494 | New
PM-6 | 9.83593 | New
PM-6 | 5.79037 | New
PM-6 | 12.2724 | New
PM-6 | 12.8259 | New
PM-6 | 12.5497 | New
PM-6 | 12.4548 | New
PM-6 | 21.4308 | Existing
PM-6 | 12.4553 | New

# IfcCovering: SA- PM-7 plaat 15x15 2, PM-7
In: Esimene korrus
Type - PredefinedType: FLOORING
Classification: 1.06 IfcCoveringType.FLOORING (põrandakatted) (RKAS BIM + ARCHICAD Classification); Material: SA- PM-7 plaat 15x15
Pset_CoveringCommon - Reference: SA- PM-7 plaat 15x15; TotalThickness: 2 mm
AR_Viimistlus - 001_Nimetus: Põrandakatte materjal; 200_Materjal: Keraamika; 205_Tähis: PM-7; 215_Tulekindlusklass: puudub; 220_Viimistlus: Tehase viimistlus; 230_Niiskuskindel: yes; 900_Tootja: Topcer; 905_Mudel: 150x150x; toon 14 (tumehall); 910_Tooteinfo: https://www.topcer.com/sizes_and_shapes.php; 915_Kasutus-ja_hooldusjuhend: https://www.topcer.com/sizes_and_shapes.php; 240_Märghõõrdekindlus: Undefined; 245_Aluspind: Betoon/tasandussegu; 200_Materjal (MUDELIS): SA- PM-7 plaat 15x15; 225_Pindala: 3.7524 m2; 210_Paksus: 8 mm
AR - 001_Nimetus: Põrandakatte materjal
AC_Pset_RenovationAndPhasing - Renovation Status: New

# IfcCovering: SA- PM-7 plaat 15x15 4, PM-7
In: Teine korrus
Type - PredefinedType: FLOORING
Classification: 1.06 IfcCoveringType.FLOORING (põrandakatted) (RKAS BIM + ARCHICAD Classification); Material: SA- PM-7 plaat 15x15
Pset_CoveringCommon - Reference: SA- PM-7 plaat 15x15; TotalThickness: 4 mm
AR - 001_Nimetus: Põrandakatte materjal
AR_Viimistlus - 001_Nimetus: Põrandakatte materjal; 200_Materjal: Keraamika; 205_Tähis: PM-7; 215_Tulekindlusklass: puudub; 220_Viimistlus: Tehase viimistlus; 230_Niiskuskindel: yes; 900_Tootja: Topcer; 905_Mudel: 150x150x; toon 14 (tumehall); 910_Tooteinfo: https://www.topcer.com/sizes_and_shapes.php; 915_Kasutus-ja_hooldusjuhend: https://www.topcer.com/sizes_and_shapes.php; 240_Märghõõrdekindlus: Undefined; 245_Aluspind: Betoon/tasandussegu; 200_Materjal (MUDELIS): SA- PM-7 plaat 15x15; 225_Pindala: 2.83036 m2; 210_Paksus: 8 mm
AC_Pset_RenovationAndPhasing - Renovation Status: New

# IfcCovering: SA- PM-7 plaat 15x15 8 (9)
Type - PredefinedType: FLOORING
Classification: 1.06 IfcCoveringType.FLOORING (põrandakatted) (RKAS BIM + ARCHICAD Classification); Material: SA- PM-7 plaat 15x15
Pset_CoveringCommon - Reference: SA- PM-7 plaat 15x15; TotalThickness: 8 mm
AR_Viimistlus - 001_Nimetus: Põrandakatte materjal; 200_Materjal: Keraamika; 205_Tähis: PM-7; 215_Tulekindlusklass: puudub; 220_Viimistlus: Tehase viimistlus; 230_Niiskuskindel: yes; 900_Tootja: Topcer; 905_Mudel: 150x150x; toon 14 (tumehall); 910_Tooteinfo: https://www.topcer.com/sizes_and_shapes.php; 915_Kasutus-ja_hooldusjuhend: https://www.topcer.com/sizes_and_shapes.php; 240_Märghõõrdekindlus: Undefined; 245_Aluspind: Betoon/tasandussegu; 200_Materjal (MUDELIS): SA- PM-7 plaat 15x15; 210_Paksus: 8 mm
AR - 001_Nimetus: Põrandakatte materjal
AC_Pset_RenovationAndPhasing - Renovation Status: New
Name | In | 225_Pindala (m2)
PM-7 | Teine korrus | 5.92011
PM-7 | Esimene korrus | 7.95526
PM-7 | Esimene korrus | 4.90121
PM-7 | Esimene korrus | 14.3425
PM-7 | Esimene korrus | 6.391
PM-7 | Esimene korrus | 6.75705
PM-7 | Esimene korrus | 5.863
PM-7 | Esimene korrus | 4.25408
PM-7 | Esimene korrus | 12.2933

# IfcCovering: SA- PM-8 EPO lakk 1 (13)
In: Esimene korrus
Type - PredefinedType: FLOORING
Classification: 1.06 IfcCoveringType.FLOORING (põrandakatted) (RKAS BIM + ARCHICAD Classification); Material: SA- PM-8 EPO lakk
Pset_CoveringCommon - Reference: PM-8; TotalThickness: 1 mm
AR_Viimistlus - 001_Nimetus: Põrandakatte värv; 200_Materjal: EPO mattlakk; 205_Tähis: PM-8; 215_Tulekindlusklass: Bfl-s1; 220_Viimistlus: matt; 230_Niiskuskindel: yes; 900_Tootja: EPO Proff; 905_Mudel: Mattlakk R10 klaaskuuliga, veebaasil; 910_Tooteinfo: https://www.epoproff.ee/dekoratiivsed-epoporandad/?gclid=CjwKCAiAx_GqBhBQEiwAlDNAZmihGik9Lt0YzbhD4wr75LZ8f0Bj_JEkq3-BchY-GO7G2Z5-up8b4hoCaU4QAvD_BwE; 915_Kasutus-ja_hooldusjuhend: https://www.epoproff.ee/dekoratiivsed-epoporandad/?gclid=CjwKCAiAx_GqBhBQEiwAlDNAZmihGik9Lt0YzbhD4wr75LZ8f0Bj_JEkq3-BchY-GO7G2Z5-up8b4hoCaU4QAvD_BwE; 240_Märghõõrdekindlus: Undefined; 245_Aluspind: Tasandussegu; 200_Materjal (MUDELIS): SA- PM-8 EPO lakk; 210_Paksus: 0.5 mm
AR - 001_Nimetus: Põrandakatte värv
AC_Pset_RenovationAndPhasing - Renovation Status: New
Name | 225_Pindala (m2)
PM-8 | 75.6415
PM-8 | 32.1543
PM-8 | 3.29818
PM-8 | 0.975874
PM-8 | 36.0894
PM-8 | 18.5389
PM-8 | 0.948987
PM-8 | 68.3915
PM-8 | 1.53
PM-8 | 8.20989
PM-8 | 68.8836
PM-8 | 35.0688
PM-8 | 66.5427

# IfcCovering: SA- Plaat SM11(tumehall) 11 (5)
In: Esimene korrus
Type - PredefinedType: CLADDING
Classification: 1.05 IfcCoveringType.CLADDING (seina viimistlus) (RKAS BIM + ARCHICAD Classification); Material: SA- Plaat SM11(tumehall)
Pset_CoveringCommon - Reference: SA- Plaat SM11(tumehall); TotalThickness: 11 mm
AR - 001_Nimetus: Seinaplaat
AR_Viimistlus - 230_Niiskuskindel: no; 001_Nimetus: Seinaplaat; 900_Tootja: Topcer; 905_Mudel: Topcer150x150x8 ; toon 14; 910_Tooteinfo: https://www.topcer.com/sizes_and_shapes.php; 915_Kasutus-ja_hooldusjuhend: https://www.topcer.com/sizes_and_shapes.php; 200_Materjal (MUDELIS): SA- Plaat SM11(tumehall)
AC_Pset_RenovationAndPhasing - Renovation Status: New
Name | 225_Pindala (m2)
SM11 | 4.30668
SM11 | 3.1832
SM11 | 3.97536
SM11 | 0
SM11 | 6.2404

# IfcCovering: SA- Plaat SM11(tumehall) 5 (4)
In: Esimene korrus
Type - PredefinedType: CLADDING
Classification: 1.05 IfcCoveringType.CLADDING (seina viimistlus) (RKAS BIM + ARCHICAD Classification); Material: SA- Plaat SM11(tumehall)
AR_Viimistlus - 230_Niiskuskindel: no; 001_Nimetus: Seinaplaat; 900_Tootja: Topcer; 905_Mudel: Topcer150x150x8 ; toon 14; 910_Tooteinfo: https://www.topcer.com/sizes_and_shapes.php; 915_Kasutus-ja_hooldusjuhend: https://www.topcer.com/sizes_and_shapes.php; 200_Materjal (MUDELIS): SA- Plaat SM11(tumehall)
AR - 001_Nimetus: Seinaplaat
AC_Pset_RenovationAndPhasing - Renovation Status: New
Pset_CoveringCommon - Reference: SA- Plaat SM11(tumehall); TotalThickness: 5 mm
Name | 225_Pindala (m2)
SM11 | 6.6642
SM11 | 0
SM11 | 5.0151
SM11 | 6.65814

# IfcCovering: SA- Plaat SM9(hele) 11 (2)
In: Esimene korrus
Type - PredefinedType: CLADDING
Classification: 1.05 IfcCoveringType.CLADDING (seina viimistlus) (RKAS BIM + ARCHICAD Classification); Material: SA- Plaat SM9(hele)
AC_Pset_RenovationAndPhasing - Renovation Status: New
AR - 001_Nimetus: Täismassplaat
Pset_CoveringCommon - Reference: SA- Plaat SM9(hele); TotalThickness: 11 mm
AR_Viimistlus - 230_Niiskuskindel: no; 001_Nimetus: Täismassplaat; 900_Tootja: Topcer; 905_Mudel: 150x150 ; toon 16 (soe valge); 910_Tooteinfo: https://www.topcer.com/sizes_and_shapes.php; 915_Kasutus-ja_hooldusjuhend: https://www.topcer.com/sizes_and_shapes.php; 200_Materjal (MUDELIS): SA- Plaat SM9(hele)
Name | 225_Pindala (m2)
SM9 | 6.92346
SM9 | 6.91389

# IfcCovering: SA- Plaat SM9(hele) 5 (3)
In: Esimene korrus
Type - PredefinedType: CLADDING
Classification: 1.05 IfcCoveringType.CLADDING (seina viimistlus) (RKAS BIM + ARCHICAD Classification); Material: SA- Plaat SM9(hele)
AR_Viimistlus - 230_Niiskuskindel: no; 001_Nimetus: Täismassplaat; 900_Tootja: Topcer; 905_Mudel: 150x150 ; toon 16 (soe valge); 910_Tooteinfo: https://www.topcer.com/sizes_and_shapes.php; 915_Kasutus-ja_hooldusjuhend: https://www.topcer.com/sizes_and_shapes.php; 200_Materjal (MUDELIS): SA- Plaat SM9(hele)
AR - 001_Nimetus: Täismassplaat
AC_Pset_RenovationAndPhasing - Renovation Status: New
Pset_CoveringCommon - Reference: SA- Plaat SM9(hele); TotalThickness: 5 mm
Name | 225_Pindala (m2)
SM9 | 2.93721
SM9 | 1.49077
SM9 | 2.62378

# IfcCovering: SA- Puitribi SM1(puitribi) (7)
In: Esimene korrus
Type - PredefinedType: CLADDING
Classification: 1.05 IfcCoveringType.CLADDING (seina viimistlus) (RKAS BIM + ARCHICAD Classification); Material: SA- Puitribi SM1(puitribi)
AR_Viimistlus - 001_Nimetus: Seinapaneel; 200_Materjal: Akustiline vilt, spoon; 205_Tähis: SM1; 215_Tulekindlusklass: B-s1,d0; 220_Viimistlus: Tehase viimistlus; 230_Niiskuskindel: no; 900_Tootja: Vaga; 905_Mudel: Vesi; 910_Tooteinfo: https://vaga-panel.ee/vaga-vesi/; 915_Kasutus-ja_hooldusjuhend: https://vaga-panel.ee/vaga-vesi/; 240_Märghõõrdekindlus: Undefined; 245_Aluspind: Viimistletud sein; 200_Materjal (MUDELIS): SA- Puitribi SM1(puitribi); 210_Paksus: 23 mm
Pset_CoveringCommon - Reference: L123
AC_Pset_RenovationAndPhasing - Renovation Status: New
AR - 001_Nimetus: Seinapaneel

# IfcCovering: SA- Puitribi SM1(puitribi) 20, SM1
In: Teine korrus
Type - PredefinedType: CLADDING
Classification: 1.05 IfcCoveringType.CLADDING (seina viimistlus) (RKAS BIM + ARCHICAD Classification); Material: SA- Puitribi SM1(puitribi)
AR_Viimistlus - 230_Niiskuskindel: no; 001_Nimetus: Akustiline seinapaneel; 900_Tootja: Vaga; 905_Mudel: Vaga Vesi; 910_Tooteinfo: https://vaga-panel.ee/vaga-vesi/; 915_Kasutus-ja_hooldusjuhend: https://vaga-panel.ee/vaga-vesi/; 200_Materjal (MUDELIS): SA- Puitribi SM1(puitribi); 225_Pindala: 16.3829 m2
Pset_CoveringCommon - Reference: SA- Puitribi SM1(puitribi); TotalThickness: 20 mm
AR - 001_Nimetus: Akustiline seinapaneel
AC_Pset_RenovationAndPhasing - Renovation Status: New

# IfcCovering: SA- Värv SM10(tumehall) 5 (19)
Type - PredefinedType: CLADDING
Classification: 1.05 IfcCoveringType.CLADDING (seina viimistlus) (RKAS BIM + ARCHICAD Classification); Material: SA- Värv SM10(tumehall)
Pset_CoveringCommon - TotalThickness: 5 mm
AR_Viimistlus - 001_Nimetus: Seinavärv; 200_Materjal: Veepõhine värv; 230_Niiskuskindel: no; 900_Tootja: Tikkurila; 910_Tooteinfo: https://tikkurila.ee/; 915_Kasutus-ja_hooldusjuhend: https://tikkurila.ee/; 240_Märghõõrdekindlus: 1.klass; 200_Materjal (MUDELIS): SA- Värv SM10(tumehall); 210_Paksus: 1 mm
AR - 001_Nimetus: Seinavärv
AC_Pset_RenovationAndPhasing - Renovation Status: New
Name | In | Reference | 205_Tähis | 215_Tulekindlusklass | 220_Viimistlus | 905_Mudel | 245_Aluspind | 225_Pindala (m2)
SM10 | Teine korrus | SA- Värv SM10(tumehall) | SM-10 | B-s1, d0 | Poolmatt NCS S 7502-y (soe pruunikas must) | Vivacolor Interior | Pahteldatud kipsplaat/sein | 0.125543
SM10 | Teine korrus | SA- Värv SM10(tumehall) | SM-10 | B-s1, d0 | Poolmatt NCS S 7502-y (soe pruunikas must) | Vivacolor Interior | Pahteldatud kipsplaat/sein | 0.152026
SM10 | Teine korrus | SA- Värv SM10(tumehall) | SM-10 | B-s1, d0 | Poolmatt NCS S 7502-y (soe pruunikas must) | Vivacolor Interior | Pahteldatud kipsplaat/sein | 0.816485
SM10 | Teine korrus | SA- Värv SM10(tumehall) | SM-10 | B-s1, d0 | Poolmatt NCS S 7502-y (soe pruunikas must) | Vivacolor Interior | Pahteldatud kipsplaat/sein | 3.65076
SM10 | Esimene korrus | SA- Värv SM10(tumehall) | SM-10 | B-s1, d0 | Poolmatt NCS S 7502-y (soe pruunikas must) | Vivacolor Interior | Pahteldatud kipsplaat/sein | 0.780658
SM10 | Esimene korrus | SA- Värv SM10(tumehall) | SM-10 | B-s1, d0 | Poolmatt NCS S 7502-y (soe pruunikas must) | Vivacolor Interior | Pahteldatud kipsplaat/sein | 0.603496
SM10 | Esimene korrus | SA- Värv SM10(tumehall) | SM-10 | B-s1, d0 | Poolmatt NCS S 7502-y (soe pruunikas must) | Vivacolor Interior | Pahteldatud kipsplaat/sein | 10.8149
SM10 | Esimene korrus | SA- Värv SM10(tumehall) | SM-10 | B-s1, d0 | Poolmatt NCS S 7502-y (soe pruunikas must) | Vivacolor Interior | Pahteldatud kipsplaat/sein | 3.03479
SM10 | Esimene korrus | SA- Värv SM10(tumehall) | SM-10 | B-s1, d0 | Poolmatt NCS S 7502-y (soe pruunikas must) | Vivacolor Interior | Pahteldatud kipsplaat/sein | 0.4318
SM10 | Esimene korrus | SA- Värv SM10(tumehall) | SM-10 | B-s1, d0 | Poolmatt NCS S 7502-y (soe pruunikas must) | Vivacolor Interior | Pahteldatud kipsplaat/sein | 0.0667134
SM10 | Esimene korrus | SA- Värv SM10(tumehall) | SM10 | B-s1,d0 | Poolmatt NCS S 7502-y (soe pruunikas must) | Vivacolor | Pahteldatud kipsplaat/sein | 1.67706
SM10 | Esimene korrus | SA- Värv SM10(tumehall) | SM-10 | B-s1, d0 | Poolmatt NCS S 7502-y (soe pruunikas must) | Vivacolor Interior | Pahteldatud kipsplaat/sein | 1.53318
SM10 | Esimene korrus | SA- Värv SM10(tumehall) | SM-10 | B-s1, d0 | Poolmatt NCS S 7502-y (soe pruunikas must) | Vivacolor Interior | Pahteldatud kipsplaat/sein | 2.61802
SM10 | Esimene korrus | SA- Värv SM10(tumehall) | SM-10 | B-s1, d0 | Poolmatt NCS S 7502-y (soe pruunikas must) | Vivacolor Interior | Pahteldatud kipsplaat/sein | 1.14956
SM10 | Esimene korrus | SA- Värv SM10(tumehall) | SM-10 | B-s1, d0 | Poolmatt NCS S 7502-y (soe pruunikas must) | Vivacolor Interior | Pahteldatud kipsplaat/sein | 1.12629
SM10 | Esimene korrus | SM5 | SM-5 | B-s1, d0 | Poolmatt NCS S 1002-y20r (soe valge) | Vivacolor Interior | pahteldatud kipsplaat/sein | 8.17132
SM10 | Esimene korrus | SA- Värv SM10(tumehall) | SM-10 | B-s1, d0 | Poolmatt NCS S 7502-y (soe pruunikas must) | Vivacolor Interior | Pahteldatud kipsplaat/sein | 7.66357
SM10 | Esimene korrus | SA- Värv SM10(tumehall) | SM-10 | B-s1, d0 | Poolmatt NCS S 7502-y (soe pruunikas must) | Vivacolor Interior | Pahteldatud kipsplaat/sein | 0.569645
SM10 | Esimene korrus | SA- Värv SM10(tumehall) | SM-10 | B-s1, d0 | Poolmatt NCS S 7502-y (soe pruunikas must) | Vivacolor Interior | Pahteldatud kipsplaat/sein | 0.73905

# IfcCovering: SA- Värv SM10(tumehall) 5 (2)
In: Esimene korrus
Type - PredefinedType: FLOORING
Classification: 1.06 IfcCoveringType.FLOORING (põrandakatted) (RKAS BIM + ARCHICAD Classification); Material: SA- Värv SM10(tumehall)
Pset_CoveringCommon - Reference: SA- Värv SM10(tumehall); TotalThickness: 5 mm
AR_Viimistlus - 001_Nimetus: Seinavärv; 200_Materjal: Veepõhine värv; 205_Tähis: SM10; 215_Tulekindlusklass: B-s1,d0; 220_Viimistlus: Poolmatt NCS S 7502-y (soe pruunikas must); 230_Niiskuskindel: no; 900_Tootja: Tikkurila; 905_Mudel: Vivacolor; 910_Tooteinfo: https://tikkurila.ee/; 915_Kasutus-ja_hooldusjuhend: https://tikkurila.ee/; 240_Märghõõrdekindlus: 1.klass; 245_Aluspind: Pahteldatud kipsplaat/sein; 200_Materjal (MUDELIS): SA- Värv SM10(tumehall); 210_Paksus: 1 mm
AR - 001_Nimetus: Seinavärv
AC_Pset_RenovationAndPhasing - Renovation Status: Existing
Name | 225_Pindala (m2)
SM10 | 0.109798
SM10 | 0.230636

# IfcCovering: SA- Värv SM12(tolmutõke) 5 (34)
In: Esimene korrus
Type - PredefinedType: CLADDING
Classification: 1.05 IfcCoveringType.CLADDING (seina viimistlus) (RKAS BIM + ARCHICAD Classification); Material: SA- Värv SM12(tolmutõke)
AR_Viimistlus - 230_Niiskuskindel: no; 001_Nimetus: Seinavärv; 900_Tootja: Tikkurila; 905_Mudel: Vivacolor; 910_Tooteinfo: https://tikkurila.ee/; 915_Kasutus-ja_hooldusjuhend: https://tikkurila.ee/; 200_Materjal (MUDELIS): SA- Värv SM12(tolmutõke)
AR - 001_Nimetus: Seinavärv
AC_Pset_RenovationAndPhasing - Renovation Status: New
Pset_CoveringCommon - Reference: SA- Värv SM12(tolmutõke); TotalThickness: 5 mm
Name | 225_Pindala (m2)
SM12 | 1.04482
SM12 | 11.2673
SM12 | 8.49881
SM12 | 1.24362
SM12 | 4.80269
SM12 | 15.0027
SM12 | 0.96294
SM12 | 0.186535
SM12 | 0.81375
SM12 | 10.1592
SM12 | 1.21586
SM12 | 6.29906
SM12 | 0.0797749
SM12 | 0.08007
SM12 | 41.0328
SM12 | 38.0361
SM12 | 11.6984
SM12 | 16.9319
SM12 | 17.2005
SM12 | 8.3111
SM12 | 0.947495
SM12 | 0.94479
SM12 | 11.927
SM12 | 6.40415
SM12 | 19.3289
SM12 | 23.1261
SM12 | 1.52294
SM12 | 0.936845
SM12 | 7.60665
SM12 | 41.059
SM12 | 15.0029
SM12 | 10.2549
SM12 | 2.31275
SM12 | 23.4034

# IfcCovering: SA- Värv SM4(Niiskuskindel värv) 5 (50)
Type - PredefinedType: CLADDING
Classification: 1.05 IfcCoveringType.CLADDING (seina viimistlus) (RKAS BIM + ARCHICAD Classification); Material: SA- Värv SM4(Niiskuskindel värv)
AR_Viimistlus - 230_Niiskuskindel: no; 001_Nimetus: Seinavärv; 900_Tootja: Tikkurila; 905_Mudel: Vivacolor Interior; 910_Tooteinfo: https://tikkurila.ee/; 915_Kasutus-ja_hooldusjuhend: https://tikkurila.ee/; 200_Materjal (MUDELIS): SA- Värv SM4(Niiskuskindel värv)
Pset_CoveringCommon - TotalThickness: 5 mm
AR - 001_Nimetus: Seinavärv
AC_Pset_RenovationAndPhasing - Renovation Status: New
Name | In | 225_Pindala (m2) | Reference
SM4 | Teine korrus | 5.75737 | SM4
SM4 | Teine korrus | 1.06664 | SM4
SM4 | Teine korrus | 5.74141 | SM4
SM4 | Teine korrus | 1.24043 | SM4
SM4 | Esimene korrus | 7.58458 | SM4
SM4 | Esimene korrus | 7.30675 | SM4
SM4 | Esimene korrus | 4.64457 | SM4
SM4 | Esimene korrus | 6.08658 | SM4
SM4 | Esimene korrus | 7.32145 | SM4
SM4 | Esimene korrus | 3.99235 | SM4
SM4 | Esimene korrus | 4.01798 | SM4
SM4 | Esimene korrus | 4.74515 | SM4
SM4 | Esimene korrus | 0.000585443 | SM4
SM4 | Esimene korrus | 0.495088 | SM4
SM4 | Esimene korrus | 0.000573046 | SM4
SM4 | Esimene korrus | 0.256744 | SM4
SM4 | Esimene korrus | 4.12292 | SM4
SM4 | Esimene korrus | 3.01109 | SM4
SM4 | Esimene korrus | 3.36588 | SM4
SM4 | Esimene korrus | 3.37272 | SM4
SM4 | Esimene korrus | 1.28619 | SM4
SM4 | Esimene korrus | 2.12075 | SM4
SM4 | Esimene korrus | 4.41276 | SM4
SM4 | Esimene korrus | 0.449803 | SM4
SM4 | Esimene korrus | 0.53855 | SM4
SM4 | Esimene korrus | 2.12706 | SM4
SM4 | Esimene korrus | 1.29298 | SM4
SM4 | Esimene korrus | 8.48568 | SM4
SM4 | Esimene korrus | 1.3082 | SM4
SM4 | Esimene korrus | 2.74186 | SM4
SM4 | Esimene korrus | 0.95777 | SM4
SM4 | Esimene korrus | 0.172321 | SM4
SM4 | Esimene korrus | 4.18785 | SM4
SM4 | Esimene korrus | 16.1931 | SM4
SM4 | Esimene korrus | 0.693088 | SM4
SM4 | Esimene korrus | 4.09711 | SM4
SM4 | Esimene korrus | 10.1732 | SM4
SM4 | Esimene korrus | 28.5734 | SM4
SM4 | Esimene korrus | 10.5482 | SM4
SM4 | Esimene korrus | 10.4209 | SM4
SM4 | Esimene korrus | 0.302542 | SM4
SM4 | Esimene korrus | 19.9099 | SM4
SM4 | Esimene korrus | 0 | SM4
SM4 | Esimene korrus | 6.706 | SM4
SM4 | Esimene korrus | 0.773163 | SM4
SM4 | Esimene korrus | 16.3651 | SM4
SM4 | Esimene korrus | 16.1433 | SM4
SM4 | Esimene korrus | 16.6021 | SM4
SM4 | Esimene korrus | 16.7506 | SM4
SM5 | Esimene korrus | 0 | SM5 | AR_Viimistlus - 200_Materjal: Veepõhine värv; 205_Tähis: SM-5; 215_Tulekindlusklass: B-s1, d0; 220_Viimistlus: Poolmatt NCS S 1002-y20r (soe valge); 240_Märghõõrdekindlus: 1.klass; 245_Aluspind: pahteldatud kipsplaat/sein; 210_Paksus: 1 mm

# IfcCovering: SA- Värv SM5(valge), SM5
In: Esimene korrus
Type - PredefinedType: CLADDING
Classification: 1.05 IfcCoveringType.CLADDING (seina viimistlus) (RKAS BIM + ARCHICAD Classification); Material: SA- Värv SM5(valge)
AR_Viimistlus - 001_Nimetus: Seinavärv; 200_Materjal: Veepõhine värv; 205_Tähis: SM5; 215_Tulekindlusklass: B-s1,d0; 220_Viimistlus: Poolmatt NCS S 1002-y20r (soe valge); 230_Niiskuskindel: no; 900_Tootja: Tikkurila; 905_Mudel: Vivacolor interior; 910_Tooteinfo: https://tikkurila.ee/; 915_Kasutus-ja_hooldusjuhend: https://tikkurila.ee/; 240_Märghõõrdekindlus: 1.klass; 245_Aluspind: Pahteldatud kipsplaat/sein; 200_Materjal (MUDELIS): SA- Värv SM5(valge); 210_Paksus: 1 mm
Pset_CoveringCommon - Reference: SM5
AR - 001_Nimetus: Seinavärv
AC_Pset_RenovationAndPhasing - Renovation Status: New

# IfcCovering: SA- Värv SM5(valge) 5 (166)
Type - PredefinedType: CLADDING
Classification: 1.05 IfcCoveringType.CLADDING (seina viimistlus) (RKAS BIM + ARCHICAD Classification); Material: SA- Värv SM5(valge)
Pset_CoveringCommon - TotalThickness: 5 mm
AR_Viimistlus - 230_Niiskuskindel: no; 200_Materjal (MUDELIS): SA- Värv SM5(valge)
AC_Pset_RenovationAndPhasing - Renovation Status: New
Name | In | Reference | AR_Viimistlus, 001_Nimetus = AR, 001_Nimetus | 200_Materjal | 205_Tähis | 215_Tulekindlusklass | 220_Viimistlus | 900_Tootja | 905_Mudel | 910_Tooteinfo = 915_Kasutus-ja_hooldusjuhend | 240_Märghõõrdekindlus | 245_Aluspind | 225_Pindala (m2) | 210_Paksus (mm)
SM5 | Teine korrus | SA- Värv SM5(valge) | Seinavärv | Veepõhine värv | SM-5 | B-s1, d0 | Poolmatt NCS S 1002-y20r (soe valge) | Tikkurila | Vivacolor Interior | https://tikkurila.ee/ | 1.klass | pahteldatud kipsplaat/sein | 3.48356 | 1
SM5 | Teine korrus | SA- Värv SM5(valge) | Seinavärv | Veepõhine värv | SM-5 | B-s1, d0 | Poolmatt NCS S 1002-y20r (soe valge) | Tikkurila | Vivacolor Interior | https://tikkurila.ee/ | 1.klass | pahteldatud kipsplaat/sein | 0.157186 | 1
3 x SM5 | Teine korrus | SA- Värv SM5(valge) | Seinavärv | Veepõhine värv | SM-5 | B-s1, d0 | Poolmatt NCS S 1002-y20r (soe valge) | Tikkurila | Vivacolor Interior | https://tikkurila.ee/ | 1.klass | pahteldatud kipsplaat/sein | 0.930018 | 1
SM5 | Teine korrus | SA- Värv SM5(valge) | Seinavärv | Veepõhine värv | SM-5 | B-s1, d0 | Poolmatt NCS S 1002-y20r (soe valge) | Tikkurila | Vivacolor Interior | https://tikkurila.ee/ | 1.klass | pahteldatud kipsplaat/sein | 0.254118 | 1
SM5 | Teine korrus | SA- Värv SM5(valge) | Seinavärv | Veepõhine värv | SM-5 | B-s1, d0 | Poolmatt NCS S 1002-y20r (soe valge) | Tikkurila | Vivacolor Interior | https://tikkurila.ee/ | 1.klass | pahteldatud kipsplaat/sein | 11.0153 | 1
SM5 | Teine korrus | SA- Värv SM5(valge) | Seinavärv | Veepõhine värv | SM-5 | B-s1, d0 | Poolmatt NCS S 1002-y20r (soe valge) | Tikkurila | Vivacolor Interior | https://tikkurila.ee/ | 1.klass | pahteldatud kipsplaat/sein | 0.157187 | 1
SM5 | Teine korrus | SA- Värv SM5(valge) | Seinavärv | Veepõhine värv | SM5 | B-s1, d0 | Poolmatt NCS S 1002-y20r (soe valge) | Tikkurila | Vivacolor Interior | https://tikkurila.ee/ | 1.klass | pahteldatud kipsplaat/sein | 16.0286 | 1
SM5 | Teine korrus | SA- Värv SM5(valge) | Seinavärv | Veepõhine värv | SM-5 | B-s1, d0 | Poolmatt NCS S 1002-y20r (soe valge) | Tikkurila | Vivacolor Interior | https://tikkurila.ee/ | 1.klass | pahteldatud kipsplaat/sein | 8.52399 | 1
SM5 | Teine korrus | SA- Värv SM5(valge) | Seinavärv | Veepõhine värv | SM5 | B-s1, d0 | Poolmatt NCS S 1002-y20r (soe valge) | Tikkurila | Vivacolor Interior | https://tikkurila.ee/ | 1.klass | pahteldatud kipsplaat/sein | 4.43156 | 1
SM5 | Teine korrus | SA- Värv SM5(valge) | Seinavärv | Veepõhine värv | SM-5 | B-s1, d0 | Poolmatt NCS S 1002-y20r (soe valge) | Tikkurila | Vivacolor Interior | https://tikkurila.ee/ | 1.klass | pahteldatud kipsplaat/sein | 7.93759 | 1
SM5 | Teine korrus | SA- Värv SM5(valge) | Seinavärv | Veepõhine värv | SM5 | B-s1, d0 | Poolmatt NCS S 1002-y20r (soe valge) | Tikkurila | Vivacolor Interior | https://tikkurila.ee/ | 1.klass | pahteldatud kipsplaat/sein | 0.799056 | 1
SM5 | Teine korrus | SA- Värv SM5(valge) | Seinavärv | Veepõhine värv | SM5 | B-s1, d0 | Poolmatt NCS S 1002-y20r (soe valge) | Tikkurila | Vivacolor Interior | https://tikkurila.ee/ | 1.klass | pahteldatud kipsplaat/sein | 0.13099 | 1
SM5 | Teine korrus | SA- Värv SM5(valge) | Seinavärv | Veepõhine värv | SM5 | B-s1, d0 | Poolmatt NCS S 1002-y20r (soe valge) | Tikkurila | Vivacolor Interior | https://tikkurila.ee/ | 1.klass | pahteldatud kipsplaat/sein | 15.0638 | 1
SM5 | Teine korrus | SA- Värv SM5(valge) | Seinavärv | Veepõhine värv | SM5 | B-s1, d0 | Poolmatt NCS S 1002-y20r (soe valge) | Tikkurila | Vivacolor Interior | https://tikkurila.ee/ | 1.klass | pahteldatud kipsplaat/sein | 0.7884 | 1
SM5 | Teine korrus | SA- Värv SM5(valge) | Seinavärv | Veepõhine värv | SM-5 | B-s1, d0 | Poolmatt NCS S 1002-y20r (soe valge) | Tikkurila | Vivacolor Interior | https://tikkurila.ee/ | 1.klass | pahteldatud kipsplaat/sein | 14.8412 | 1
SM5 | Teine korrus | SA- Värv SM5(valge) | Seinavärv | Veepõhine värv | SM5 | B-s1, d0 | Poolmatt NCS S 1002-y20r (soe valge) | Tikkurila | Vivacolor Interior | https://tikkurila.ee/ | 1.klass | pahteldatud kipsplaat/sein | 0.80804 | 1
SM5 | Teine korrus | SA- Värv SM5(valge) | Seinavärv | Veepõhine värv | SM-5 | B-s1, d0 | Poolmatt NCS S 1002-y20r (soe valge) | Tikkurila | Vivacolor Interior | https://tikkurila.ee/ | 1.klass | pahteldatud kipsplaat/sein | 9.74575 | 1
SM5 | Teine korrus | SA- Värv SM5(valge) | Seinavärv | Veepõhine värv | SM-5 | B-s1, d0 | Poolmatt NCS S 1002-y20r (soe valge) | Tikkurila | Vivacolor Interior | https://tikkurila.ee/ | 1.klass | pahteldatud kipsplaat/sein | 0.501955 | 1
2 x SM5 | Teine korrus | SA- Värv SM5(valge) | Seinavärv | Veepõhine värv | SM-5 | B-s1, d0 | Poolmatt NCS S 1002-y20r (soe valge) | Tikkurila | Vivacolor Interior | https://tikkurila.ee/ | 1.klass | pahteldatud kipsplaat/sein | 1.47607 | 1
SM5 | Teine korrus | SA- Värv SM5(valge) | Seinavärv | Veepõhine värv | SM-5 | B-s1, d0 | Poolmatt NCS S 1002-y20r (soe valge) | Tikkurila | Vivacolor Interior | https://tikkurila.ee/ | 1.klass | pahteldatud kipsplaat/sein | 7.85089 | 1
SM5 | Teine korrus | SA- Värv SM5(valge) | Seinavärv | Veepõhine värv | SM-5 | B-s1, d0 | Poolmatt NCS S 1002-y20r (soe valge) | Tikkurila | Vivacolor Interior | https://tikkurila.ee/ | 1.klass | pahteldatud kipsplaat/sein | 0.765479 | 1
SM5 | Teine korrus | SA- Värv SM5(valge) | Seinavärv | Veepõhine värv | SM-5 | B-s1, d0 | Poolmatt NCS S 1002-y20r (soe valge) | Tikkurila | Vivacolor Interior | https://tikkurila.ee/ | 1.klass | pahteldatud kipsplaat/sein | 0.890968 | 1
SM5 | Teine korrus | SA- Värv SM5(valge) | Seinavärv | Veepõhine värv | SM-5 | B-s1, d0 | Poolmatt NCS S 1002-y20r (soe valge) | Tikkurila | Vivacolor Interior | https://tikkurila.ee/ | 1.klass | pahteldatud kipsplaat/sein | 10.8824 | 1
SM5 | Teine korrus | SA- Värv SM5(valge) | Seinavärv | Veepõhine värv | SM-5 | B-s1, d0 | Poolmatt NCS S 1002-y20r (soe valge) | Tikkurila | Vivacolor Interior | https://tikkurila.ee/ | 1.klass | pahteldatud kipsplaat/sein | 8.93478 | 1
SM5 | Teine korrus | SA- Värv SM5(valge) | Seinavärv | Veepõhine värv | SM-5 | B-s1, d0 | Poolmatt NCS S 1002-y20r (soe valge) | Tikkurila | Vivacolor Interior | https://tikkurila.ee/ | 1.klass | pahteldatud kipsplaat/sein | 7.95915 | 1
SM5 | Teine korrus | SA- Värv SM5(valge) | Seinavärv | Veepõhine värv | SM-5 | B-s1, d0 | Poolmatt NCS S 1002-y20r (soe valge) | Tikkurila | Vivacolor Interior | https://tikkurila.ee/ | 1.klass | pahteldatud kipsplaat/sein | 7.58179 | 1
SM5 | Teine korrus | SA- Värv SM5(valge) | Seinavärv | Veepõhine värv | SM-5 | B-s1, d0 | Poolmatt NCS S 1002-y20r (soe valge) | Tikkurila | Vivacolor Interior | https://tikkurila.ee/ | 1.klass | pahteldatud kipsplaat/sein | 11.5865 | 1
SM5 | Teine korrus | SA- Värv SM5(valge) | Seinavärv | Veepõhine värv | SM-5 | B-s1, d0 | Poolmatt NCS S 1002-y20r (soe valge) | Tikkurila | Vivacolor Interior | https://tikkurila.ee/ | 1.klass | pahteldatud kipsplaat/sein | 11.4534 | 1
SM5 | Teine korrus | SA- Värv SM5(valge) | Seinavärv | Veepõhine värv | SM-5 | B-s1, d0 | Poolmatt NCS S 1002-y20r (soe valge) | Tikkurila | Vivacolor Interior | https://tikkurila.ee/ | 1.klass | pahteldatud kipsplaat/sein | 12.5811 | 1
SM5 | Teine korrus | SA- Värv SM5(valge) | Seinavärv | Veepõhine värv | SM-5 | B-s1, d0 | Poolmatt NCS S 1002-y20r (soe valge) | Tikkurila | Vivacolor Interior | https://tikkurila.ee/ | 1.klass | pahteldatud kipsplaat/sein | 12.0159 | 1
SM5 | Teine korrus | SA- Värv SM5(valge) | Seinavärv | Veepõhine värv | SM-5 | B-s1, d0 | Poolmatt NCS S 1002-y20r (soe valge) | Tikkurila | Vivacolor Interior | https://tikkurila.ee/ | 1.klass | pahteldatud kipsplaat/sein | 0.799029 | 1
SM5 | Teine korrus | SA- Värv SM5(valge) | Seinavärv | Veepõhine värv | SM-5 | B-s1, d0 | Poolmatt NCS S 1002-y20r (soe valge) | Tikkurila | Vivacolor Interior | https://tikkurila.ee/ | 1.klass | pahteldatud kipsplaat/sein | 7.6135 | 1
SM5 | Teine korrus | SA- Värv SM5(valge) | Seinavärv | Veepõhine värv | SM-5 | B-s1, d0 | Poolmatt NCS S 1002-y20r (soe valge) | Tikkurila | Vivacolor Interior | https://tikkurila.ee/ | 1.klass | pahteldatud kipsplaat/sein | 1.5379 | 1
SM5 | Teine korrus | SA- Värv SM5(valge) | Seinavärv | Veepõhine värv | SM-5 | B-s1, d0 | Poolmatt NCS S 1002-y20r (soe valge) | Tikkurila | Vivacolor Interior | https://tikkurila.ee/ | 1.klass | pahteldatud kipsplaat/sein | 9.18519 | 1
SM5 | Teine korrus | SA- Värv SM5(valge) | Seinavärv | Veepõhine värv | SM-5 | B-s1, d0 | Poolmatt NCS S 1002-y20r (soe valge) | Tikkurila | Vivacolor Interior | https://tikkurila.ee/ | 1.klass | pahteldatud kipsplaat/sein | 0 | 1
SM5 | Teine korrus | SA- Värv SM5(valge) | Seinavärv | Veepõhine värv | SM-5 | B-s1, d0 | Poolmatt NCS S 1002-y20r (soe valge) | Tikkurila | Vivacolor Interior | https://tikkurila.ee/ | 1.klass | pahteldatud kipsplaat/sein | 16.026 | 1
SM5 | Teine korrus | SA- Värv SM5(valge) | Seinavärv | Veepõhine värv | SM-5 | B-s1, d0 | Poolmatt NCS S 1002-y20r (soe valge) | Tikkurila | Vivacolor Interior | https://tikkurila.ee/ | 1.klass | pahteldatud kipsplaat/sein | 0.854302 | 1
SM5 | Teine korrus | SA- Värv SM5(valge) | Seinavärv | Veepõhine värv | SM-5 | B-s1, d0 | Poolmatt NCS S 1002-y20r (soe valge) | Tikkurila | Vivacolor Interior | https://tikkurila.ee/ | 1.klass | pahteldatud kipsplaat/sein | 6.44331 | 1
SM5 | Teine korrus | SA- Värv SM5(valge) | Seinavärv | Veepõhine värv | SM-5 | B-s1, d0 | Poolmatt NCS S 1002-y20r (soe valge) | Tikkurila | Vivacolor Interior | https://tikkurila.ee/ | 1.klass | pahteldatud kipsplaat/sein | 7.05468 | 1
SM5 | Teine korrus | SA- Värv SM5(valge) | Seinavärv | Veepõhine värv | SM-5 | B-s1, d0 | Poolmatt NCS S 1002-y20r (soe valge) | Tikkurila | Vivacolor Interior | https://tikkurila.ee/ | 1.klass | pahteldatud kipsplaat/sein | 0.912268 | 1
SM5 | Teine korrus | SA- Värv SM5(valge) | Seinavärv | Veepõhine värv | SM-5 | B-s1, d0 | Poolmatt NCS S 1002-y20r (soe valge) | Tikkurila | Vivacolor Interior | https://tikkurila.ee/ | 1.klass | pahteldatud kipsplaat/sein | 8.23737 | 1
SM5 | Teine korrus | SA- Värv SM5(valge) | Seinavärv | Veepõhine värv | SM-5 | B-s1, d0 | Poolmatt NCS S 1002-y20r (soe valge) | Tikkurila | Vivacolor Interior | https://tikkurila.ee/ | 1.klass | pahteldatud kipsplaat/sein | 7.21296 | 1
SM5 | Teine korrus | SA- Värv SM5(valge) | Seinavärv | Veepõhine värv | SM-5 | B-s1, d0 | Poolmatt NCS S 1002-y20r (soe valge) | Tikkurila | Vivacolor Interior | https://tikkurila.ee/ | 1.klass | pahteldatud kipsplaat/sein | 1.49797 | 1
SM5 | Teine korrus | SA- Värv SM5(valge) | Seinavärv | Veepõhine värv | SM-5 | B-s1, d0 | Poolmatt NCS S 1002-y20r (soe valge) | Tikkurila | Vivacolor Interior | https://tikkurila.ee/ | 1.klass | pahteldatud kipsplaat/sein | 2.8846 | 1
SM5 | Teine korrus | SA- Värv SM5(valge) | Seinavärv | Veepõhine värv | SM-5 | B-s1, d0 | Poolmatt NCS S 1002-y20r (soe valge) | Tikkurila | Vivacolor Interior | https://tikkurila.ee/ | 1.klass | pahteldatud kipsplaat/sein | 7.47423 | 1
SM5 | Teine korrus | SA- Värv SM5(valge) | Seinavärv | Veepõhine värv | SM-5 | B-s1, d0 | Poolmatt NCS S 1002-y20r (soe valge) | Tikkurila | Vivacolor Interior | https://tikkurila.ee/ | 1.klass | pahteldatud kipsplaat/sein | 0.130988 | 1
SM5 | Teine korrus | SA- Värv SM5(valge) | Seinavärv | Veepõhine värv | SM-5 | B-s1, d0 | Poolmatt NCS S 1002-y20r (soe valge) | Tikkurila | Vivacolor Interior | https://tikkurila.ee/ | 1.klass | pahteldatud kipsplaat/sein | 7.20504 | 1
SM5 | Teine korrus | SA- Värv SM5(valge) | Seinavärv | Veepõhine värv | SM-5 | B-s1, d0 | Poolmatt NCS S 1002-y20r (soe valge) | Tikkurila | Vivacolor Interior | https://tikkurila.ee/ | 1.klass | pahteldatud kipsplaat/sein | 7.58155 | 1
SM5 | Teine korrus | SA- Värv SM5(valge) | Seinavärv | Veepõhine värv | SM-5 | B-s1, d0 | Poolmatt NCS S 1002-y20r (soe valge) | Tikkurila | Vivacolor Interior | https://tikkurila.ee/ | 1.klass | pahteldatud kipsplaat/sein | 13.8765 | 1
SM5 | Teine korrus | SA- Värv SM5(valge) | Seinavärv | Veepõhine värv | SM-5 | B-s1, d0 | Poolmatt NCS S 1002-y20r (soe valge) | Tikkurila | Vivacolor Interior | https://tikkurila.ee/ | 1.klass | pahteldatud kipsplaat/sein | 17.973 | 1
SM5 | Teine korrus | SA- Värv SM5(valge) | Seinavärv | Veepõhine värv | SM-5 | B-s1, d0 | Poolmatt NCS S 1002-y20r (soe valge) | Tikkurila | Vivacolor Interior | https://tikkurila.ee/ | 1.klass | pahteldatud kipsplaat/sein | 0.950059 | 1
SM5 | Teine korrus | SA- Värv SM5(valge) | Seinavärv | Veepõhine värv | SM-5 | B-s1, d0 | Poolmatt NCS S 1002-y20r (soe valge) | Tikkurila | Vivacolor Interior | https://tikkurila.ee/ | 1.klass | pahteldatud kipsplaat/sein | 1.53654 | 1
SM5 | Teine korrus | SA- Värv SM5(valge) | Seinavärv | Veepõhine värv | SM-5 | B-s1, d0 | Poolmatt NCS S 1002-y20r (soe valge) | Tikkurila | Vivacolor Interior | https://tikkurila.ee/ | 1.klass | pahteldatud kipsplaat/sein | 7.59311 | 1
SM5 | Teine korrus | SA- Värv SM5(valge) | Seinavärv | Veepõhine värv | SM-5 | B-s1, d0 | Poolmatt NCS S 1002-y20r (soe valge) | Tikkurila | Vivacolor Interior | https://tikkurila.ee/ | 1.klass | pahteldatud kipsplaat/sein | 8.87753 | 1
SM5 | Teine korrus | SA- Värv SM5(valge) | Seinavärv | Veepõhine värv | SM-5 | B-s1, d0 | Poolmatt NCS S 1002-y20r (soe valge) | Tikkurila | Vivacolor Interior | https://tikkurila.ee/ | 1.klass | pahteldatud kipsplaat/sein | 7.58777 | 1
SM5 | Teine korrus | SA- Värv SM5(valge) | Seinavärv | Veepõhine värv | SM-5 | B-s1, d0 | Poolmatt NCS S 1002-y20r (soe valge) | Tikkurila | Vivacolor Interior | https://tikkurila.ee/ | 1.klass | pahteldatud kipsplaat/sein | 0.816485 | 1
SM5 | Teine korrus | SA- Värv SM5(valge) | Seinavärv | Veepõhine värv | SM-5 | B-s1, d0 | Poolmatt NCS S 1002-y20r (soe valge) | Tikkurila | Vivacolor Interior | https://tikkurila.ee/ | 1.klass | pahteldatud kipsplaat/sein | 16.5853 | 1
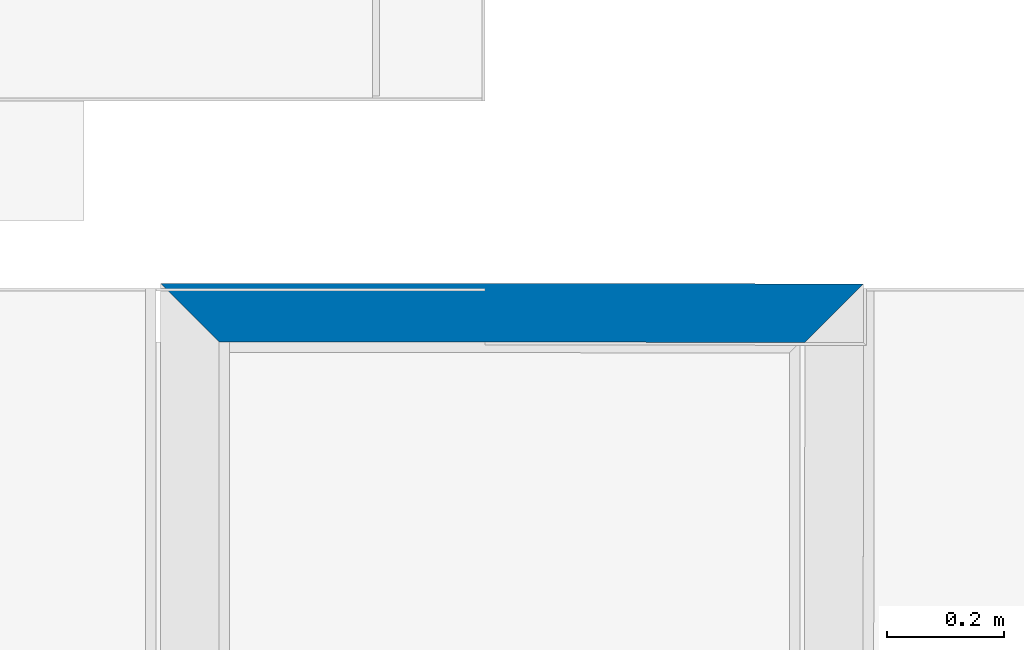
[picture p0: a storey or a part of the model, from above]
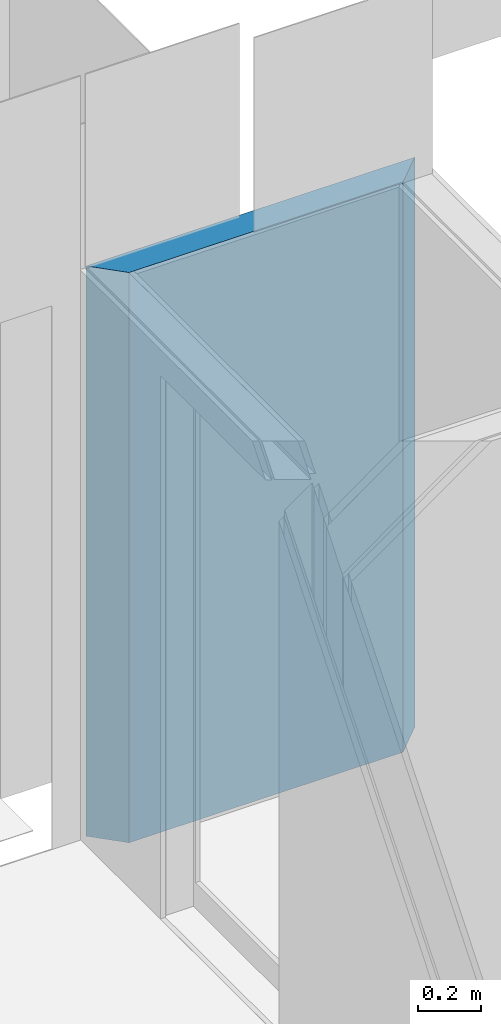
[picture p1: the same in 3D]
Properties of the parts of a building model (IFC2X3), part 2 of 2

# IfcCovering: SA- Värv SM5(valge) 5 (166)
Name | In | Reference | AR_Viimistlus, 001_Nimetus = AR, 001_Nimetus | 200_Materjal | 205_Tähis | 215_Tulekindlusklass | 220_Viimistlus | 900_Tootja | 905_Mudel | 910_Tooteinfo = 915_Kasutus-ja_hooldusjuhend | 240_Märghõõrdekindlus | 245_Aluspind | 225_Pindala (m2) | 210_Paksus (mm)
SM5 | Teine korrus | SA- Värv SM5(valge) | Seinavärv | Veepõhine värv | SM-5 | B-s1, d0 | Poolmatt NCS S 1002-y20r (soe valge) | Tikkurila | Vivacolor Interior | https://tikkurila.ee/ | 1.klass | pahteldatud kipsplaat/sein | 0.160323 | 1
SM1 | Esimene korrus | SA- Värv SM5(valge) | SM1 |  |  |  |  | Undefined | Undefined | https://vaga-panel.ee/vaga-vesi/ |  |  | 0.186614
SM4 | Esimene korrus | SM4 | Seinavärv |  |  |  |  | Tikkurila | Vivacolor Interior | https://tikkurila.ee/ |  |  | 1.02403
SM4 | Esimene korrus | SM4 | Seinavärv |  |  |  |  | Tikkurila | Vivacolor Interior | https://tikkurila.ee/ |  |  | 1.00637
SM5 | Esimene korrus | SM5 | Seinavärv | Veepõhine värv | SM-5 | B-s1, d0 | Poolmatt NCS S 1002-y20r (soe valge) | Tikkurila | Vivacolor Interior | https://tikkurila.ee/ | 1.klass | pahteldatud kipsplaat/sein | 12.3728 | 1
SM5 | Esimene korrus | SM5 | Seinavärv | Veepõhine värv | SM-5 | B-s1, d0 | Poolmatt NCS S 1002-y20r (soe valge) | Tikkurila | Vivacolor Interior | https://tikkurila.ee/ | 1.klass | pahteldatud kipsplaat/sein | 2.79477 | 1
SM5 | Esimene korrus | SM5 | Seinavärv | Veepõhine värv | SM-5 | B-s1, d0 | Poolmatt NCS S 1002-y20r (soe valge) | Tikkurila | Vivacolor Interior | https://tikkurila.ee/ | 1.klass | pahteldatud kipsplaat/sein | 0.13335 | 1
2 x SM5 | Esimene korrus | SM5 | Seinavärv | Veepõhine värv | SM-5 | B-s1, d0 | Poolmatt NCS S 1002-y20r (soe valge) | Tikkurila | Vivacolor Interior | https://tikkurila.ee/ | 1.klass | pahteldatud kipsplaat/sein | 10.8149 | 1
SM5 | Esimene korrus | SM5 | Seinavärv | Veepõhine värv | SM-5 | B-s1, d0 | Poolmatt NCS S 1002-y20r (soe valge) | Tikkurila | Vivacolor Interior | https://tikkurila.ee/ | 1.klass | pahteldatud kipsplaat/sein | 4.99646 | 1
4 x SM5 | Esimene korrus | SM5 | Seinavärv | Veepõhine värv | SM-5 | B-s1, d0 | Poolmatt NCS S 1002-y20r (soe valge) | Tikkurila | Vivacolor Interior | https://tikkurila.ee/ | 1.klass | pahteldatud kipsplaat/sein | 1.53317 | 1
SM5 | Esimene korrus | SM5 | Seinavärv | Veepõhine värv | SM-5 | B-s1, d0 | Poolmatt NCS S 1002-y20r (soe valge) | Tikkurila | Vivacolor Interior | https://tikkurila.ee/ | 1.klass | pahteldatud kipsplaat/sein | 3.90437 | 1
SM5 | Esimene korrus | SM5 | Seinavärv | Veepõhine värv | SM-5 | B-s1, d0 | Poolmatt NCS S 1002-y20r (soe valge) | Tikkurila | Vivacolor Interior | https://tikkurila.ee/ | 1.klass | pahteldatud kipsplaat/sein | 13.5372 | 1
SM5 | Esimene korrus | SM5 | Seinavärv | Veepõhine värv | SM-5 | B-s1, d0 | Poolmatt NCS S 1002-y20r (soe valge) | Tikkurila | Vivacolor Interior | https://tikkurila.ee/ | 1.klass | pahteldatud kipsplaat/sein | 3.93091 | 1
SM5 | Esimene korrus | SM5 | Seinavärv | Veepõhine värv | SM-5 | B-s1, d0 | Poolmatt NCS S 1002-y20r (soe valge) | Tikkurila | Vivacolor Interior | https://tikkurila.ee/ | 1.klass | pahteldatud kipsplaat/sein | 10.3864 | 1
2 x SM5 | Esimene korrus | SM5 | Seinavärv | Veepõhine värv | SM-5 | B-s1, d0 | Poolmatt NCS S 1002-y20r (soe valge) | Tikkurila | Vivacolor Interior | https://tikkurila.ee/ | 1.klass | pahteldatud kipsplaat/sein | 0.173355 | 1
SM5 | Esimene korrus | SM5 | Seinavärv | Veepõhine värv | SM-5 | B-s1, d0 | Poolmatt NCS S 1002-y20r (soe valge) | Tikkurila | Vivacolor Interior | https://tikkurila.ee/ | 1.klass | pahteldatud kipsplaat/sein | 0.040005 | 1
SM5 | Esimene korrus | SM5 | Seinavärv | Veepõhine värv | SM-5 | B-s1, d0 | Poolmatt NCS S 1002-y20r (soe valge) | Tikkurila | Vivacolor Interior | https://tikkurila.ee/ | 1.klass | pahteldatud kipsplaat/sein | 11.1807 | 1
SM5 | Esimene korrus | SM5 | Seinavärv | Veepõhine värv | SM-5 | B-s1, d0 | Poolmatt NCS S 1002-y20r (soe valge) | Tikkurila | Vivacolor Interior | https://tikkurila.ee/ | 1.klass | pahteldatud kipsplaat/sein | 10.8282 | 1
SM5 | Esimene korrus | SM5 | Seinavärv | Veepõhine värv | SM-5 | B-s1, d0 | Poolmatt NCS S 1002-y20r (soe valge) | Tikkurila | Vivacolor Interior | https://tikkurila.ee/ | 1.klass | pahteldatud kipsplaat/sein | 13.5363 | 1
SM5 | Esimene korrus | SM5 | Seinavärv | Veepõhine värv | SM-5 | B-s1, d0 | Poolmatt NCS S 1002-y20r (soe valge) | Tikkurila | Vivacolor Interior | https://tikkurila.ee/ | 1.klass | pahteldatud kipsplaat/sein | 8.37874 | 1
2 x SM5 | Esimene korrus | SM5 | Seinavärv | Veepõhine värv | SM-5 | B-s1, d0 | Poolmatt NCS S 1002-y20r (soe valge) | Tikkurila | Vivacolor Interior | https://tikkurila.ee/ | 1.klass | pahteldatud kipsplaat/sein | 0 | 1
SM5 | Esimene korrus | SA- Värv SM5(valge) | Seinavärv | Veepõhine värv | SM-5 | B-s1, d0 | Poolmatt NCS S 1002-y20r (soe valge) | Tikkurila | Vivacolor Interior | https://tikkurila.ee/ | 1.klass | pahteldatud kipsplaat/sein | 0.418574 | 1
SM5 | Esimene korrus | SA- Värv SM5(valge) | Seinavärv | Veepõhine värv | SM-5 | B-s1, d0 | Poolmatt NCS S 1002-y20r (soe valge) | Tikkurila | Vivacolor Interior | https://tikkurila.ee/ | 1.klass | pahteldatud kipsplaat/sein | 0.122855 | 1
SM5 | Esimene korrus | SM5 | Seinavärv | Veepõhine värv | SM-5 | B-s1, d0 | Poolmatt NCS S 1002-y20r (soe valge) | Tikkurila | Vivacolor Interior | https://tikkurila.ee/ | 1.klass | pahteldatud kipsplaat/sein | 12.1003 | 1
SM5 | Esimene korrus | SA- Värv SM5(valge) | Seinavärv | Veepõhine värv | SM-5 | B-s1, d0 | Poolmatt NCS S 1002-y20r (soe valge) | Tikkurila | Vivacolor Interior | https://tikkurila.ee/ | 1.klass | pahteldatud kipsplaat/sein | 0.485208 | 1
SM5 | Esimene korrus | SM5 | Seinavärv | Veepõhine värv | SM-5 | B-s1, d0 | Poolmatt NCS S 1002-y20r (soe valge) | Tikkurila | Vivacolor Interior | https://tikkurila.ee/ | 1.klass | pahteldatud kipsplaat/sein | 2.11045 | 1
SM5 | Esimene korrus | SM5 | Seinavärv | Veepõhine värv | SM-5 | B-s1, d0 | Poolmatt NCS S 1002-y20r (soe valge) | Tikkurila | Vivacolor Interior | https://tikkurila.ee/ | 1.klass | pahteldatud kipsplaat/sein | 1.26529 | 1
SM5 | Esimene korrus | SM5 | Seinavärv | Veepõhine värv | SM-5 | B-s1, d0 | Poolmatt NCS S 1002-y20r (soe valge) | Tikkurila | Vivacolor Interior | https://tikkurila.ee/ | 1.klass | pahteldatud kipsplaat/sein | 5.76335 | 1
SM5 | Esimene korrus | SM5 | Seinavärv | Veepõhine värv | SM-5 | B-s1, d0 | Poolmatt NCS S 1002-y20r (soe valge) | Tikkurila | Vivacolor Interior | https://tikkurila.ee/ | 1.klass | pahteldatud kipsplaat/sein | 3.95209 | 1
SM5 | Esimene korrus | SM5 | Seinavärv | Veepõhine värv | SM-5 | B-s1, d0 | Poolmatt NCS S 1002-y20r (soe valge) | Tikkurila | Vivacolor Interior | https://tikkurila.ee/ | 1.klass | pahteldatud kipsplaat/sein | 2.77906 | 1
SM5 | Esimene korrus | SA- Värv SM5(valge) | Seinavärv | Veepõhine värv | SM-5 | B-s1, d0 | Poolmatt NCS S 1002-y20r (soe valge) | Tikkurila | Vivacolor Interior | https://tikkurila.ee/ | 1.klass | pahteldatud kipsplaat/sein | 0.2935 | 1
SM5 | Esimene korrus | SM5 | Seinavärv | Veepõhine värv | SM-5 | B-s1, d0 | Poolmatt NCS S 1002-y20r (soe valge) | Tikkurila | Vivacolor Interior | https://tikkurila.ee/ | 1.klass | pahteldatud kipsplaat/sein | 3.77778 | 1
SM5 | Esimene korrus | SM5 | Seinavärv | Veepõhine värv | SM-5 | B-s1, d0 | Poolmatt NCS S 1002-y20r (soe valge) | Tikkurila | Vivacolor Interior | https://tikkurila.ee/ | 1.klass | pahteldatud kipsplaat/sein | 0.96294 | 1
SM5 | Esimene korrus | SM5 | Seinavärv | Veepõhine värv | SM-5 | B-s1, d0 | Poolmatt NCS S 1002-y20r (soe valge) | Tikkurila | Vivacolor Interior | https://tikkurila.ee/ | 1.klass | pahteldatud kipsplaat/sein | 3.38488 | 1
SM5 | Esimene korrus | SM5 | Seinavärv | Veepõhine värv | SM-5 | B-s1, d0 | Poolmatt NCS S 1002-y20r (soe valge) | Tikkurila | Vivacolor Interior | https://tikkurila.ee/ | 1.klass | pahteldatud kipsplaat/sein | 1.80708 | 1
SM5 | Esimene korrus | SA- Värv SM5(valge) | Seinavärv | Veepõhine värv | SM-5 | B-s1, d0 | Poolmatt NCS S 1002-y20r (soe valge) | Tikkurila | Vivacolor Interior | https://tikkurila.ee/ | 1.klass | pahteldatud kipsplaat/sein | 0.94785 | 1
SM5 | Esimene korrus | SM5 | Seinavärv | Veepõhine värv | SM-5 | B-s1, d0 | Poolmatt NCS S 1002-y20r (soe valge) | Tikkurila | Vivacolor Interior | https://tikkurila.ee/ | 1.klass | pahteldatud kipsplaat/sein | 3.83227 | 1
SM5 | Esimene korrus | SM5 | Seinavärv | Veepõhine värv | SM-5 | B-s1, d0 | Poolmatt NCS S 1002-y20r (soe valge) | Tikkurila | Vivacolor Interior | https://tikkurila.ee/ | 1.klass | pahteldatud kipsplaat/sein | 12.534 | 1
SM5 | Esimene korrus | SM5 | Seinavärv | Veepõhine värv | SM-5 | B-s1, d0 | Poolmatt NCS S 1002-y20r (soe valge) | Tikkurila | Vivacolor Interior | https://tikkurila.ee/ | 1.klass | pahteldatud kipsplaat/sein | 2.90755 | 1
SM5 | Esimene korrus | SM5 | Seinavärv | Veepõhine värv | SM-5 | B-s1, d0 | Poolmatt NCS S 1002-y20r (soe valge) | Tikkurila | Vivacolor Interior | https://tikkurila.ee/ | 1.klass | pahteldatud kipsplaat/sein | 1.26552 | 1
SM5 | Esimene korrus | SM5 | Seinavärv | Veepõhine värv | SM-5 | B-s1, d0 | Poolmatt NCS S 1002-y20r (soe valge) | Tikkurila | Vivacolor Interior | https://tikkurila.ee/ | 1.klass | pahteldatud kipsplaat/sein | 10.8404 | 1
SM5 | Esimene korrus | SM5 | Seinavärv | Veepõhine värv | SM-5 | B-s1, d0 | Poolmatt NCS S 1002-y20r (soe valge) | Tikkurila | Vivacolor Interior | https://tikkurila.ee/ | 1.klass | pahteldatud kipsplaat/sein | 0.8046 | 1
SM5 | Esimene korrus | SM5 | Seinavärv | Veepõhine värv | SM-5 | B-s1, d0 | Poolmatt NCS S 1002-y20r (soe valge) | Tikkurila | Vivacolor Interior | https://tikkurila.ee/ | 1.klass | pahteldatud kipsplaat/sein | 5.24587 | 1
SM5 | Esimene korrus | SM5 | Seinavärv | Veepõhine värv | SM-5 | B-s1, d0 | Poolmatt NCS S 1002-y20r (soe valge) | Tikkurila | Vivacolor Interior | https://tikkurila.ee/ | 1.klass | pahteldatud kipsplaat/sein | 0.936845 | 1
SM5 | Esimene korrus | SM5 | Seinavärv | Veepõhine värv | SM-5 | B-s1, d0 | Poolmatt NCS S 1002-y20r (soe valge) | Tikkurila | Vivacolor Interior | https://tikkurila.ee/ | 1.klass | pahteldatud kipsplaat/sein | 19.8993 | 1
SM5 | Esimene korrus | SM5 | Seinavärv | Veepõhine värv | SM-5 | B-s1, d0 | Poolmatt NCS S 1002-y20r (soe valge) | Tikkurila | Vivacolor Interior | https://tikkurila.ee/ | 1.klass | pahteldatud kipsplaat/sein | 5.14843 | 1
SM5 | Esimene korrus | SM5 | Seinavärv | Veepõhine värv | SM-5 | B-s1, d0 | Poolmatt NCS S 1002-y20r (soe valge) | Tikkurila | Vivacolor Interior | https://tikkurila.ee/ | 1.klass | pahteldatud kipsplaat/sein | 10.0435 | 1
SM5 | Esimene korrus | SM5 | Seinavärv | Veepõhine värv | SM-5 | B-s1, d0 | Poolmatt NCS S 1002-y20r (soe valge) | Tikkurila | Vivacolor Interior | https://tikkurila.ee/ | 1.klass | pahteldatud kipsplaat/sein | 10.3709 | 1
SM5 | Esimene korrus | SM5 | Seinavärv | Veepõhine värv | SM-5 | B-s1, d0 | Poolmatt NCS S 1002-y20r (soe valge) | Tikkurila | Vivacolor Interior | https://tikkurila.ee/ | 1.klass | pahteldatud kipsplaat/sein | 8.40409 | 1
SM5 | Esimene korrus | SM5 | Seinavärv | Veepõhine värv | SM-5 | B-s1, d0 | Poolmatt NCS S 1002-y20r (soe valge) | Tikkurila | Vivacolor Interior | https://tikkurila.ee/ | 1.klass | pahteldatud kipsplaat/sein | 15.3116 | 1
SM5 | Esimene korrus | SM5 | Seinavärv | Veepõhine värv | SM-5 | B-s1, d0 | Poolmatt NCS S 1002-y20r (soe valge) | Tikkurila | Vivacolor Interior | https://tikkurila.ee/ | 1.klass | pahteldatud kipsplaat/sein | 0.46597 | 1
SM5 | Esimene korrus | SM5 | Seinavärv | Veepõhine värv | SM-5 | B-s1, d0 | Poolmatt NCS S 1002-y20r (soe valge) | Tikkurila | Vivacolor Interior | https://tikkurila.ee/ | 1.klass | pahteldatud kipsplaat/sein | 18.9172 | 1
SM5 | Esimene korrus | SM5 | Seinavärv | Veepõhine värv | SM-5 | B-s1, d0 | Poolmatt NCS S 1002-y20r (soe valge) | Tikkurila | Vivacolor Interior | https://tikkurila.ee/ | 1.klass | pahteldatud kipsplaat/sein | 11.6914 | 1
SM5 | Esimene korrus | SM5 | Seinavärv | Veepõhine värv | SM-5 | B-s1, d0 | Poolmatt NCS S 1002-y20r (soe valge) | Tikkurila | Vivacolor Interior | https://tikkurila.ee/ | 1.klass | pahteldatud kipsplaat/sein | 9.68099 | 1
SM5 | Esimene korrus | SM5 | Seinavärv | Veepõhine värv | SM-5 | B-s1, d0 | Poolmatt NCS S 1002-y20r (soe valge) | Tikkurila | Vivacolor Interior | https://tikkurila.ee/ | 1.klass | pahteldatud kipsplaat/sein | 0.17319 | 1
SM5 | Esimene korrus | SM5 | Seinavärv | Veepõhine värv | SM-5 | B-s1, d0 | Poolmatt NCS S 1002-y20r (soe valge) | Tikkurila | Vivacolor Interior | https://tikkurila.ee/ | 1.klass | pahteldatud kipsplaat/sein | 16.0391 | 1
SM5 | Esimene korrus | SM5 | Seinavärv | Veepõhine värv | SM-5 | B-s1, d0 | Poolmatt NCS S 1002-y20r (soe valge) | Tikkurila | Vivacolor Interior | https://tikkurila.ee/ | 1.klass | pahteldatud kipsplaat/sein | 6.65185 | 1
SM5 | Esimene korrus | SM5 | Seinavärv | Veepõhine värv | SM-5 | B-s1, d0 | Poolmatt NCS S 1002-y20r (soe valge) | Tikkurila | Vivacolor Interior | https://tikkurila.ee/ | 1.klass | pahteldatud kipsplaat/sein | 6.67948 | 1
2 x SM5 | Esimene korrus | SM5 | Seinavärv | Veepõhine värv | SM-5 | B-s1, d0 | Poolmatt NCS S 1002-y20r (soe valge) | Tikkurila | Vivacolor Interior | https://tikkurila.ee/ | 1.klass | pahteldatud kipsplaat/sein | 0.95559 | 1
SM5 | Esimene korrus | SA- Värv SM5(valge) | Seinavärv | Veepõhine värv | SM-5 | B-s1, d0 | Poolmatt NCS S 1002-y20r (soe valge) | Tikkurila | Vivacolor Interior | https://tikkurila.ee/ | 1.klass | pahteldatud kipsplaat/sein | 0.69682 | 1
SM5 | Esimene korrus | SM5 | Seinavärv | Veepõhine värv | SM-5 | B-s1, d0 | Poolmatt NCS S 1002-y20r (soe valge) | Tikkurila | Vivacolor Interior | https://tikkurila.ee/ | 1.klass | pahteldatud kipsplaat/sein | 7.24967 | 1
SM5 | Esimene korrus | SM5 | Seinavärv | Veepõhine värv | SM-5 | B-s1, d0 | Poolmatt NCS S 1002-y20r (soe valge) | Tikkurila | Vivacolor Interior | https://tikkurila.ee/ | 1.klass | pahteldatud kipsplaat/sein | 2.69277 | 1
3 x SM5 | Esimene korrus | SM5 | Seinavärv | Veepõhine värv | SM-5 | B-s1, d0 | Poolmatt NCS S 1002-y20r (soe valge) | Tikkurila | Vivacolor Interior | https://tikkurila.ee/ | 1.klass | pahteldatud kipsplaat/sein | 0.974633 | 1
SM5 | Esimene korrus | SM5 | Seinavärv | Veepõhine värv | SM-5 | B-s1, d0 | Poolmatt NCS S 1002-y20r (soe valge) | Tikkurila | Vivacolor Interior | https://tikkurila.ee/ | 1.klass | pahteldatud kipsplaat/sein | 8.16594 | 1
2 x SM5 | Esimene korrus | SM5 | Seinavärv | Veepõhine värv | SM-5 | B-s1, d0 | Poolmatt NCS S 1002-y20r (soe valge) | Tikkurila | Vivacolor Interior | https://tikkurila.ee/ | 1.klass | pahteldatud kipsplaat/sein | 0.173485 | 1
SM5 | Esimene korrus | SM5 | Seinavärv | Veepõhine värv | SM-5 | B-s1, d0 | Poolmatt NCS S 1002-y20r (soe valge) | Tikkurila | Vivacolor Interior | https://tikkurila.ee/ | 1.klass | pahteldatud kipsplaat/sein | 0.186535 | 1
SM5 | Esimene korrus | SM5 | Seinavärv | Veepõhine värv | SM-5 | B-s1, d0 | Poolmatt NCS S 1002-y20r (soe valge) | Tikkurila | Vivacolor Interior | https://tikkurila.ee/ | 1.klass | pahteldatud kipsplaat/sein | 2.66251 | 1
SM5 | Esimene korrus | SM5 | Seinavärv | Veepõhine värv | SM-5 | B-s1, d0 | Poolmatt NCS S 1002-y20r (soe valge) | Tikkurila | Vivacolor Interior | https://tikkurila.ee/ | 1.klass | pahteldatud kipsplaat/sein | 15.1439 | 1
SM5 | Esimene korrus | SM5 | Seinavärv | Veepõhine värv | SM-5 | B-s1, d0 | Poolmatt NCS S 1002-y20r (soe valge) | Tikkurila | Vivacolor Interior | https://tikkurila.ee/ | 1.klass | pahteldatud kipsplaat/sein | 13.9569 | 1
SM5 | Esimene korrus | SM5 | Seinavärv | Veepõhine värv | SM-5 | B-s1, d0 | Poolmatt NCS S 1002-y20r (soe valge) | Tikkurila | Vivacolor Interior | https://tikkurila.ee/ | 1.klass | pahteldatud kipsplaat/sein | 0.346675 | 1
SM5 | Esimene korrus | SM5 | Seinavärv | Veepõhine värv | SM-5 | B-s1, d0 | Poolmatt NCS S 1002-y20r (soe valge) | Tikkurila | Vivacolor Interior | https://tikkurila.ee/ | 1.klass | pahteldatud kipsplaat/sein | 0.347039 | 1
SM5 | Esimene korrus | SM5 | Seinavärv | Veepõhine värv | SM-5 | B-s1, d0 | Poolmatt NCS S 1002-y20r (soe valge) | Tikkurila | Vivacolor Interior | https://tikkurila.ee/ | 1.klass | pahteldatud kipsplaat/sein | 17.0414 | 1
SM5 | Esimene korrus | SM5 | Seinavärv | Veepõhine värv | SM-5 | B-s1, d0 | Poolmatt NCS S 1002-y20r (soe valge) | Tikkurila | Vivacolor Interior | https://tikkurila.ee/ | 1.klass | pahteldatud kipsplaat/sein | 0.11981 | 1
SM5 | Esimene korrus | SM5 | Seinavärv | Veepõhine värv | SM-5 | B-s1, d0 | Poolmatt NCS S 1002-y20r (soe valge) | Tikkurila | Vivacolor Interior | https://tikkurila.ee/ | 1.klass | pahteldatud kipsplaat/sein | 7.83476 | 1
SM5 | Esimene korrus | SM5 | Seinavärv | Veepõhine värv | SM-5 | B-s1, d0 | Poolmatt NCS S 1002-y20r (soe valge) | Tikkurila | Vivacolor Interior | https://tikkurila.ee/ | 1.klass | pahteldatud kipsplaat/sein | 11.6511 | 1
SM5 | Esimene korrus | SM5 | Seinavärv | Veepõhine värv | SM-5 | B-s1, d0 | Poolmatt NCS S 1002-y20r (soe valge) | Tikkurila | Vivacolor Interior | https://tikkurila.ee/ | 1.klass | pahteldatud kipsplaat/sein | 5.87422 | 1
SM5 | Esimene korrus | SM5 | Seinavärv | Veepõhine värv | SM-5 | B-s1, d0 | Poolmatt NCS S 1002-y20r (soe valge) | Tikkurila | Vivacolor Interior | https://tikkurila.ee/ | 1.klass | pahteldatud kipsplaat/sein | 11.8162 | 1
SM5 | Esimene korrus | SM5 | Seinavärv | Veepõhine värv | SM-5 | B-s1, d0 | Poolmatt NCS S 1002-y20r (soe valge) | Tikkurila | Vivacolor Interior | https://tikkurila.ee/ | 1.klass | pahteldatud kipsplaat/sein | 2.76579 | 1
SM5 | Esimene korrus | SM5 | Seinavärv | Veepõhine värv | SM-5 | B-s1, d0 | Poolmatt NCS S 1002-y20r (soe valge) | Tikkurila | Vivacolor Interior | https://tikkurila.ee/ | 1.klass | pahteldatud kipsplaat/sein | 11.7612 | 1
SM5 | Esimene korrus | SM5 | Seinavärv | Veepõhine värv | SM-5 | B-s1, d0 | Poolmatt NCS S 1002-y20r (soe valge) | Tikkurila | Vivacolor Interior | https://tikkurila.ee/ | 1.klass | pahteldatud kipsplaat/sein | 0.173486 | 1
SM5 | Esimene korrus | SM5 | Seinavärv | Veepõhine värv | SM-5 | B-s1, d0 | Poolmatt NCS S 1002-y20r (soe valge) | Tikkurila | Vivacolor Interior | https://tikkurila.ee/ | 1.klass | pahteldatud kipsplaat/sein | 2.46905 | 1
SM5 | Esimene korrus | SM5 | Seinavärv | Veepõhine värv | SM-5 | B-s1, d0 | Poolmatt NCS S 1002-y20r (soe valge) | Tikkurila | Vivacolor Interior | https://tikkurila.ee/ | 1.klass | pahteldatud kipsplaat/sein | 0.224222 | 1
SM5 | Esimene korrus | SM5 | Seinavärv | Veepõhine värv | SM-5 | B-s1, d0 | Poolmatt NCS S 1002-y20r (soe valge) | Tikkurila | Vivacolor Interior | https://tikkurila.ee/ | 1.klass | pahteldatud kipsplaat/sein | 7.53599 | 1
SM5 | Esimene korrus | SM5 | Seinavärv | Veepõhine värv | SM-5 | B-s1, d0 | Poolmatt NCS S 1002-y20r (soe valge) | Tikkurila | Vivacolor Interior | https://tikkurila.ee/ | 1.klass | pahteldatud kipsplaat/sein | 7.53873 | 1
SM5 | Esimene korrus | SM5 | Seinavärv | Veepõhine värv | SM-5 | B-s1, d0 | Poolmatt NCS S 1002-y20r (soe valge) | Tikkurila | Vivacolor Interior | https://tikkurila.ee/ | 1.klass | pahteldatud kipsplaat/sein | 0.226865 | 1
SM5 | Esimene korrus | SM5 | Seinavärv | Veepõhine värv | SM-5 | B-s1, d0 | Poolmatt NCS S 1002-y20r (soe valge) | Tikkurila | Vivacolor Interior | https://tikkurila.ee/ | 1.klass | pahteldatud kipsplaat/sein | 5.49062 | 1
SM5 | Esimene korrus | SM5 | Seinavärv | Veepõhine värv | SM-5 | B-s1, d0 | Poolmatt NCS S 1002-y20r (soe valge) | Tikkurila | Vivacolor Interior | https://tikkurila.ee/ | 1.klass | pahteldatud kipsplaat/sein | 5.72733 | 1
SM5 | Esimene korrus | SM5 | Seinavärv | Veepõhine värv | SM-5 | B-s1, d0 | Poolmatt NCS S 1002-y20r (soe valge) | Tikkurila | Vivacolor Interior | https://tikkurila.ee/ | 1.klass | pahteldatud kipsplaat/sein | 13.5501 | 1
SM5 | Esimene korrus | SM5 | Seinavärv | Veepõhine värv | SM-5 | B-s1, d0 | Poolmatt NCS S 1002-y20r (soe valge) | Tikkurila | Vivacolor Interior | https://tikkurila.ee/ | 1.klass | pahteldatud kipsplaat/sein | 1.06208 | 1
SM5 | Esimene korrus | SM5 | Seinavärv | Veepõhine värv | SM-5 | B-s1, d0 | Poolmatt NCS S 1002-y20r (soe valge) | Tikkurila | Vivacolor Interior | https://tikkurila.ee/ | 1.klass | pahteldatud kipsplaat/sein | 2.28781 | 1
SM5 | Esimene korrus | SM5 | Seinavärv | Veepõhine värv | SM-5 | B-s1, d0 | Poolmatt NCS S 1002-y20r (soe valge) | Tikkurila | Vivacolor Interior | https://tikkurila.ee/ | 1.klass | pahteldatud kipsplaat/sein | 4.70013 | 1
SM5 | Esimene korrus | SM5 | Seinavärv | Veepõhine värv | SM-5 | B-s1, d0 | Poolmatt NCS S 1002-y20r (soe valge) | Tikkurila | Vivacolor Interior | https://tikkurila.ee/ | 1.klass | pahteldatud kipsplaat/sein | 4.38325 | 1
SM5 | Esimene korrus | SM5 | Seinavärv | Veepõhine värv | SM-5 | B-s1, d0 | Poolmatt NCS S 1002-y20r (soe valge) | Tikkurila | Vivacolor Interior | https://tikkurila.ee/ | 1.klass | pahteldatud kipsplaat/sein | 4.22959 | 1
SM5 | Esimene korrus | SM5 | Seinavärv | Veepõhine värv | SM-5 | B-s1, d0 | Poolmatt NCS S 1002-y20r (soe valge) | Tikkurila | Vivacolor Interior | https://tikkurila.ee/ | 1.klass | pahteldatud kipsplaat/sein | 3.87223 | 1
SM5 | Esimene korrus | SM5 | Seinavärv | Veepõhine värv | SM-5 | B-s1, d0 | Poolmatt NCS S 1002-y20r (soe valge) | Tikkurila | Vivacolor Interior | https://tikkurila.ee/ | 1.klass | pahteldatud kipsplaat/sein | 7.70962 | 1
SM6 | Esimene korrus |  | Seinavärv |  |  |  |  | Tikkurila | Vivacolor Interior | https://tikkurila.ee/ |  |  | 1.52374

# IfcCovering: SA- Värv SM6(kollane) 5 (16)
Type - PredefinedType: CLADDING
Classification: 1.05 IfcCoveringType.CLADDING (seina viimistlus) (RKAS BIM + ARCHICAD Classification); Material: SA- Värv SM6(kollane)
AR_Viimistlus - 230_Niiskuskindel: no; 001_Nimetus: Seinavärv; 900_Tootja: Tikkurila; 905_Mudel: Vivacolor Interior; 910_Tooteinfo: https://tikkurila.ee/; 915_Kasutus-ja_hooldusjuhend: https://tikkurila.ee/; 200_Materjal (MUDELIS): SA- Värv SM6(kollane)
AR - 001_Nimetus: Seinavärv
Pset_CoveringCommon - TotalThickness: 5 mm
AC_Pset_RenovationAndPhasing - Renovation Status: New
Name | In | 225_Pindala (m2)
SM6 | Teine korrus | 5.34938
SM6 | Teine korrus | 14.6992
SM6 | Teine korrus | 2.87928
SM6 | Teine korrus | 5.66262
SM6 | Teine korrus | 9.266
SM6 | Teine korrus | 14.016
SM6 | Teine korrus | 13.8779
SM6 | Teine korrus | 31.5934
SM6 | Teine korrus | 5.59073
SM6 | Teine korrus | 1.60801
SM6 | Esimene korrus | 5.98507
SM6 | Esimene korrus | 4.91501
SM6 | Esimene korrus | 5.93333
SM6 | Esimene korrus | 5.88383
SM6 | Esimene korrus | 19.0215
SM6 | Esimene korrus | 8.39571

# IfcCovering: SA- Värv SM7(beez) 5 (12)
Type - PredefinedType: CLADDING
Classification: 1.05 IfcCoveringType.CLADDING (seina viimistlus) (RKAS BIM + ARCHICAD Classification); Material: SA- Värv SM7(beez)
AR_Viimistlus - 230_Niiskuskindel: no; 001_Nimetus: Seinavärv; 900_Tootja: Tikkurila; 905_Mudel: Vivacolor Interior; 910_Tooteinfo: https://tikkurila.ee/; 915_Kasutus-ja_hooldusjuhend: https://tikkurila.ee/; 200_Materjal (MUDELIS): SA- Värv SM7(beez)
Pset_CoveringCommon - Reference: SA- Värv SM7(beez); TotalThickness: 5 mm
AC_Pset_RenovationAndPhasing - Renovation Status: New
AR - 001_Nimetus: Seinavärv
Name | In | 225_Pindala (m2)
SM7 | Teine korrus | 14.4567
SM7 | Teine korrus | 3.70659
SM7 | Teine korrus | 4.77998
SM7 | Teine korrus | 59.7884
SM7 | Esimene korrus | 3.35544
SM7 | Esimene korrus | 3.45536
SM7 | Esimene korrus | 1.65925
SM7 | Esimene korrus | 8.25365
SM7 | Esimene korrus | 30.6669
SM7 | Esimene korrus | 3.77599
SM7 | Esimene korrus | 0.806065
SM7 | Esimene korrus | 0.171665

# IfcCovering: SA- Värv SM8(helebeez) 5 (6)
Type - PredefinedType: CLADDING
Classification: 1.05 IfcCoveringType.CLADDING (seina viimistlus) (RKAS BIM + ARCHICAD Classification); Material: SA- Värv SM8(helebeez)
AR_Viimistlus - 230_Niiskuskindel: no; 001_Nimetus: Seinavärv; 900_Tootja: Tikkurila; 905_Mudel: Vivacolor Interior; 910_Tooteinfo: https://tikkurila.ee/; 915_Kasutus-ja_hooldusjuhend: https://tikkurila.ee/; 200_Materjal (MUDELIS): SA- Värv SM8(helebeez)
Pset_CoveringCommon - Reference: SA- Värv SM8(helebeez); TotalThickness: 5 mm
AC_Pset_RenovationAndPhasing - Renovation Status: New
AR - 001_Nimetus: Seinavärv
Name | In | 225_Pindala (m2)
SM8 | Teine korrus | 0.296518
SM8 | Teine korrus | 15.9307
SM8 | Teine korrus | 1.13256
SM8 | Teine korrus | 31.1472
SM8 | Teine korrus | 0.706293
SM8 | Esimene korrus | 31.5452

# IfcFurnishingElement: SA- Värv SM10(tumehall), SM10
In: Esimene korrus
Classification: 1.11 IfcFurnitureType (mööbel) (RKAS BIM + ARCHICAD Classification); Material: SA- Värv SM10(tumehall)
Pset_QuantityTakeOff - Reference: SA- Värv SM10(tumehall)
AC_Pset_RenovationAndPhasing - Renovation Status: New
AR_Mööbel - 001_Nimetus: Seinavärv; 002_Tähis: SA- Värv SM10(tumehall); 900_Tootja: Tikkurila; 905_Mudel: Vivacolor Interior

# IfcOpeningElement: OPENING (148)
Classification: 1.14 IfcOpeningElement (avaelement) (RKAS BIM + ARCHICAD Classification)
AR - 001_Nimetus: AVA
Name | In | Reference | Renovation Status
AVA | Teine korrus | AVA: 2,100x1,000 | Existing
AVA | Teine korrus | AVA: 1,771x2,407 | New
AVA | Teine korrus | AVA: 2,124x949 | New
AVA | Teine korrus | AVA: 2,128x940 | New
AVA | Teine korrus | AVA: 1,753x2,409 | New
2 x AVA | Teine korrus | AVA: 1,731x2,389 | New
AVA | Teine korrus | AVA: 2,130x1,576 | New
2 x AVA | Teine korrus | AVA: 1,753x2,394 | New
2 x AVA | Teine korrus | AVA: 1,732x2,397 | New
AVA | Teine korrus | AVA: 1,756x2,399 | New
AVA | Teine korrus | AVA: 1,756x2,416 | New
2 x AVA | Teine korrus | AVA: 1,750x2,408 | New
AVA | Teine korrus | AVA: 2,191x1,069 | New
AVA | Teine korrus | AVA: 2,116x1,055 | New
2 x AVA | Teine korrus | AVA: 1,760x2,391 | New
AVA | Teine korrus | AVA: 2,080x1,000 | New
3 x AVA | Teine korrus | AVA: 1,739x2,397 | New
AVA | Teine korrus | AVA: 1,757x2,417 | New
AVA | Teine korrus | AVA: 1,757x2,401 | New
2 x AVA | Teine korrus | AVA: 1,756x2,419 | New
AVA | Teine korrus | AVA: 2,124x1,001 | New
AVA | Teine korrus | AVA: 2,128x1,058 | New
AVA | Teine korrus | AVA: 2,126x1,065 | New
AVA | Teine korrus | AVA: 2,127x1,023 | New
AVA | Teine korrus | AVA: 2,145x1,080 | New
AVA | Teine korrus | AVA: 2,100x1,095 | New
AVA | Teine korrus | AVA: 2,240x863 | New
AVA | Teine korrus | AVA: 2,100x1,076 | New
6 x AVA | Teine korrus | AVA: 2,100x1,000 | New
2 x AVA | Teine korrus | AVA: 2,097x1,000 | New
AVA | Teine korrus | AVA: 2,097x1,500 | New
AVA | Teine korrus | AVA: 2,097x1,866 | New
AVA | Teine korrus | AVA: 2,130x1,061 | New
2 x AVA | Teine korrus | AVA: 2,100x900 | New
AVA | Esimene korrus | AVA: 2,662x2,600 | New
AVA | Esimene korrus | AVA: 2,544x2,418 | New
AVA | Esimene korrus | AVA: 2,134x833 | New
AVA | Esimene korrus | AVA: 2,113x838 | New
AVA | Esimene korrus | AVA: 2,139x1,044 | New
AVA | Esimene korrus | AVA: 2,122x800 | New
AVA | Esimene korrus | AVA: 2,100x800 | New
4 x AVA | Esimene korrus | AVA: 2,100x1,500 | New
AVA | Esimene korrus | AVA: 1,686x1,475 | New
AVA | Esimene korrus | AVA: 2,600x2,988 | New
AVA | Esimene korrus | AVA: 1,694x1,423 | New
2 x AVA | Esimene korrus | AVA: 1,764x2,403 | New
AVA | Esimene korrus | AVA: 1,800x633 | New
AVA | Esimene korrus | AVA: 2,147x895 | New
AVA | Esimene korrus | AVA: 2,606x2,989 | New
AVA | Esimene korrus | AVA: 2,412x995 | New
AVA | Esimene korrus | AVA: 2,015x751 | New
AVA | Esimene korrus | AVA: 2,097x750 | New
AVA | Esimene korrus | AVA: 2,097x749 | New
AVA | Esimene korrus | AVA: 2,097x758 | New
AVA | Esimene korrus | AVA: 2,139x1,251 | New
AVA | Esimene korrus | AVA: 2,502x800 | New
AVA | Esimene korrus | AVA: 2,099x1,449 | New
AVA | Esimene korrus | AVA: 2,130x1,015 | New
AVA | Esimene korrus | AVA: 2,100x1,000 | New
AVA | Esimene korrus | AVA: 2,136x1,306 | New
AVA | Esimene korrus | AVA: 2,100x1,449 | New
AVA | Esimene korrus | AVA: 2,119x774 | New
AVA | Esimene korrus | AVA: 2,117x746 | New
AVA | Esimene korrus | AVA: 2,100x792 | New
AVA | Esimene korrus | AVA: 1,750x900 | New
AVA | Esimene korrus | AVA: 2,076x1,221 | New
AVA | Esimene korrus | AVA: 1,721x1,335 | New
AVA | Esimene korrus | AVA: 2,600x2,980 | New
AVA | Esimene korrus | AVA: 2,190x1,300 | New
AVA | Esimene korrus | AVA: 2,118x1,308 | New
AVA | Esimene korrus | AVA: 2,135x1,274 | New
AVA | Esimene korrus | AVA: 1,725x1,424 | New
AVA | Esimene korrus | AVA: 1,818x2,200 | New
2 x AVA | Esimene korrus | AVA: 1,748x2,414 | New
AVA | Esimene korrus | AVA: 1,689x1,206 | New
AVA | Esimene korrus | AVA: 2,117x1,295 | New
AVA | Esimene korrus | AVA: 1,748x2,395 | New
AVA | Esimene korrus | AVA: 2,120x979 | New
AVA | Esimene korrus | AVA: 2,000x1,472 | New
AVA | Esimene korrus | AVA: 2,139x1,277 | New
AVA | Esimene korrus | AVA: 1,752x2,397 | New
AVA | Esimene korrus | AVA: 2,150x900 | New
2 x AVA | Esimene korrus | AVA: 2,100x1,250 | New
AVA | Esimene korrus | AVA: 2,100x2,518 | New
AVA | Esimene korrus | AVA: 1,751x911 | New
AVA | Esimene korrus | AVA: 1,773x2,408 | New
AVA | Esimene korrus | AVA: 2,153x1,287 | New
AVA | Esimene korrus | AVA: 2,106x1,250 | New
AVA | Esimene korrus | AVA: 2,128x995 | New
2 x AVA | Esimene korrus | AVA: 1,750x2,399 | New
AVA | Esimene korrus | AVA: 2,142x850 | New
AVA | Esimene korrus | AVA: 2,235x1,553 | New
AVA | Esimene korrus | AVA: 1,708x1,355 | New
AVA | Esimene korrus | AVA: 870x1,450 | New
2 x AVA | Esimene korrus | AVA: 1,766x2,420 | New
AVA | Esimene korrus | AVA: 2,097x795 | New
AVA | Esimene korrus | AVA: 2,097x800 | New
AVA | Esimene korrus | AVA: 2,154x1,304 | New
AVA | Esimene korrus | AVA: 2,216x1,537 | New
AVA | Esimene korrus | AVA: 1,756x2,392 | New
AVA | Esimene korrus | AVA: 2,560x2,650 | New
AVA | Esimene korrus | AVA: 2,226x1,562 | New
AVA | Esimene korrus | AVA: 2,124x1,031 | New
AVA | Esimene korrus | AVA: 2,247x1,600 | New
AVA | Esimene korrus | AVA: 2,134x1,042 | New
AVA | Esimene korrus | AVA: 2,118x1,043 | New
AVA | Esimene korrus | AVA: 2,150x850 | New
AVA | Esimene korrus | AVA: 2,134x1,280 | New
AVA | Esimene korrus | AVA: 2,146x1,050 | New
2 x AVA | Esimene korrus | AVA: 2,137x1,092 | New
AVA | Esimene korrus | AVA: 2,142x1,072 | New
AVA | Esimene korrus | AVA: 2,139x1,261 | New
AVA | Esimene korrus | AVA: 2,139x1,081 | New
AVA | Esimene korrus | AVA: 2,097x1,300 | New
AVA | Esimene korrus | AVA: 2,133x1,297 | New
AVA | Esimene korrus | AVA: 2,133x1,285 | New
AVA | Esimene korrus | AVA: 2,154x1,055 | New
AVA | Esimene korrus | AVA: 2,154x1,081 | New
AVA | Esimene korrus | AVA: 2,192x1,250 | New
2 x AVA | Esimene korrus | AVA: 2,137x1,043 | New
AVA | Esimene korrus | AVA: 463x884 | New
AVA | Esimene korrus | AVA: 2,083x1,250 | New
AVA | Esimene korrus | AVA: 1,760x911 | New

# IfcWallStandardCase: KON-00_GENEERILINE - KONSTRUKTSIOON 100, SS-62
In: Esimene korrus
Classification: 1.24 IfcWallType (sein) (RKAS BIM + ARCHICAD Classification); Material: KON-00_GENEERILINE - KONSTRUKTSIOON 100 mm
AR_Sein - 001_Nimetus: SS-62; 325_Helipidavus: 24 dB; 330_Tulekindlus: nõudeid ei esitata; 335_Välispiire: no; 340_Soojusläbivus: 0.22; 605_Neto_pindala: 2.2 m2; 600_Bruto_pindala: 2.64 m2; 500_Kandev: no; 505_Paksus: 100 mm
Pset_WallCommon - IsExternal: no; LoadBearing: no
AC_Pset_RenovationAndPhasing - Renovation Status: Existing
